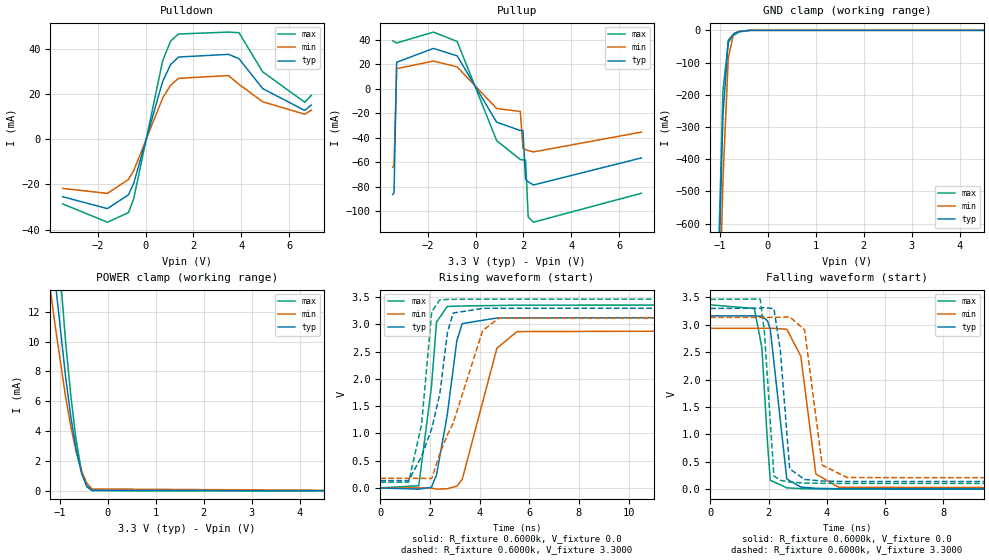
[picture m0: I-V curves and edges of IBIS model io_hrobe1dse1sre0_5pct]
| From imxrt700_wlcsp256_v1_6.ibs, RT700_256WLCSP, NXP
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[Model] io_hrobe1dse1sre0_5pct
|   Model io_hrobe1dse1sre0_5pct
| This model was characterised for following simulation conditions:
| External (pad) voltage:
|   - Typ: 3.3V,   - Min: 3.135V,   - Max: 3.465V
| Library cells for typ/min/max conditions are connected as defined below:
|  PAD_IO - External Pad
|  ipp_do - Core Input
|  ipp_obe - Output Buffer Enable
|  ASRCN3V3[3] - NC
|  ASRCN3V3[4] - NC
|  ASRCP3V3[4] - NC
|  REFAPBIAS3V3 - gnde
|  REFBAMPL3V3 - vdd1v8
|  REFCAMPH3V3 - vdd1v8
|  REFDNBIAS3V3 - vdd1v8
|  REFH3V3 - REFH3V3
|  REFL3V3 - REFL3V3
|  gnde - gnde
|  ipp_dse - vdd
|  ipp_ina235_3v - NC
|  ipp_ina40_3v - NC
|  ipp_ina_mux - NC
|  ipp_ind - NC
|  ipp_ind_1p8v - NC
|  ipp_ind_3v - NC
|  ipp_sre - gnde
|  vdd - vdd
|  vdd1v8 - vdd1v8
|  vdda - vdde3v3
|  vdde3v3 - vdde3v3
| All other pins connected to ground
Model_type I/O
Polarity   Non-Inverting
Enable   Active-High
Vinl =   0.9900V
Vinh =   2.3100V
Vmeas =  1.6500V
Cref =   15.0000pF
Rref =   0.6000k
Vref =   0.0V
C_comp   4.0008pF   3.8187pF   4.1208pF
|C_comp_pullup   0.5645pF   0.7326pF   0.4702pF
|C_comp_pulldown   2.1154pF   2.2153pF   1.8986pF
[Model Spec]
| variable   typ   min   max
Vinh   2.3100V   NA   NA
Vinl   0.9900V   NA   NA
Vref   0.0V   0.0V   0.0V
Cref   15.0000pF   15.0000pF   15.0000pF
Rref   0.6000k   0.6000k   0.6000k
[Receiver Thresholds]
Vcross_high  =   0.0V
Vcross_low  =   0.0V
Vdiff_ac  =   0.0V
Vdiff_dc  =   0.0V
Tdiffslew_ac  =   0.0S
[Temperature Range]   25.0000   0.1250k   -40.0000
[Voltage Range]   3.3000V   3.1350V   3.4650V
[Pullup Reference]   3.3000V   3.1350V   3.4650V
[Pulldown Reference]   0.0V   0.0V   0.0V
[POWER Clamp Reference]   3.3000V   3.1350V   3.4650V
[GND Clamp Reference]   0.0V   0.0V   0.0V
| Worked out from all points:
|   slope of the pulldown table from 0 to 0.495 V, typ, clamps not added: 26.4 ohm
|   slope of the pullup table from 0 to 0.495 V, typ, clamps not added: 28.4 ohm
|   GND clamp passes 1 mA (typ) near -0.50 V on its own axis
|   POWER clamp passes 1 mA (typ) near -0.52 V on its own axis
|   rising waveform, R_fixture 0.6000k, V_fixture 0.0: 20-80 % time 584ps typ, 889ps min, 429ps max; typ from 0 V to 3.16 V
|   rising waveform, R_fixture 0.6000k, V_fixture 3.3000: 20-80 % time 848ps typ, 1.35ns min, 497ps max; typ from 0.133 V to 3.3 V
|   falling waveform, R_fixture 0.6000k, V_fixture 0.0: 20-80 % time 295ps typ, 388ps min, 229ps max; typ from 3.16 V to 0 V
|   falling waveform, R_fixture 0.6000k, V_fixture 3.3000: 20-80 % time 266ps typ, 370ps min, 204ps max; typ from 3.3 V to 0.133 V
[Pulldown]
|Voltage   I(typ)   I(min)   I(max)
-3.465V   -25.43mA   -21.75mA   -28.62mA
-1.595V   -30.68mA   -23.94mA   -36.7mA
-715mV    -24.55mA   -17.79mA   -32.46mA
-495mV    -19.43mA   -13.83mA   -26.26mA
715mV     25.71mA    18.31mA    34.82mA
1.045V    33.07mA    23.94mA    43.49mA
1.375V    36.45mA    27mA       46.65mA
3.465V    37.64mA    28.25mA    47.5mA
3.905V    35.75mA    24.38mA    47.23mA
4.895V    22.48mA    16.65mA    29.91mA
6.655V    12.8mA     11.11mA    16.42mA
6.93V     15.18mA    12.92mA    19.48mA
[Pullup]
|Voltage   I(typ)   I(min)   I(max)
-3.465V   -86.4mA    -64.18mA   39.19mA
-3.41V    -84.92mA   -62.83mA   38.54mA
-3.3V     21.6mA     16.32mA    37.36mA
-1.76V    32.92mA    22.62mA    46.24mA
-770mV    26.81mA    17.8mA     38.61mA
880mV     -27.3mA    -16.17mA   -42.37mA
1.87V     -34.13mA   -18.57mA   -57.85mA
1.98V     -34.24mA   -48.76mA   -58.1mA
2.09V     -74.17mA   -49.75mA   -58.3mA
2.2V      -75.93mA   -50.54mA   -104.8mA
2.42V     -78.62mA   -51.61mA   -109mA
6.93V     -56.52mA   -35.45mA   -85.38mA
[GND_clamp]
|Voltage   I(typ)   I(min)   I(max)
-3.465V   -18.65A    -18.54A    -19.59A
-1.045V   -856.3mA   -1.07A     -789.2mA
-935mV    -262.9mA   -462.2mA   -186.4mA
-825mV    -31.14mA   -87.01mA   -37.16mA
-715mV    -11.21mA   -10.51mA   -15.88mA
-605mV    -3.859mA   -3.519mA   -5.394mA
-385mV    -79.74uA   -219.6uA   -43.96uA
6.93V     0A         0A         0A
[POWER_clamp]
|Voltage   I(typ)   I(min)   I(max)
-3.465V   98.76mA    78.08mA    125.9mA
-1.43V    25.63mA    19.65mA    34.12mA
-1.32V    21.65mA    16.67mA    28.86mA
-1.21V    17.8mA     13.81mA    23.74mA
-1.1V     14.15mA    11.1mA     18.82mA
-880mV    7.624mA    6.286mA    9.977mA
-770mV    4.936mA    4.278mA    6.317mA
-660mV    2.762mA    2.615mA    3.373mA
-550mV    1.207mA    1.351mA    1.33mA
-440mV    332.8uA    528.9uA    282.4uA
-330mV    37.59uA    131uA      15.04uA
6.93V     0A         0A         0A
[Ramp]
| variable   typ   min   max
dV/dt_r  1.8972/0.5839n   1.7621/0.8891n   2.0192/0.4291n
dV/dt_f  1.9001/0.2655n   1.7755/0.3702n   2.0172/0.2036n
R_load = 0.6000k
[Rising Waveform]
R_fixture= 0.6000k
V_fixture= 0.0
V_fixture_min= 0.0
V_fixture_max= 0.0
|time   V(typ)   V(min)   V(max)
0s        75.99nV    1.239uV    52.33nV
1.551ns   -22.58mV   -290.2uV   40.84mV
2.061ns   13.37mV    -3.702mV   1.856V
2.267ns   242.9mV    -21.67mV   3.043V
2.696ns   1.333V     -14.5mV    3.329V
3.085ns   2.704V     32.34mV    3.336V
3.301ns   3.015V     156.9mV    3.338V
4.698ns   3.118V     2.564V     3.347V
5.508ns   3.119V     2.868V     3.353V
60ns      3.162V     2.937V     3.365V
[Rising Waveform]
R_fixture= 0.6000k
V_fixture= 3.3000
V_fixture_min= 3.1350
V_fixture_max= 3.4650
|time   V(typ)   V(min)   V(max)
0s        133.2mV    175.8mV    103mV
1.142ns   132.6mV    175.8mV    106.7mV
1.661ns   578.6mV    175.7mV    1.156V
2.073ns   1.086V     172.2mV    3.234V
2.4ns     1.729V     632.4mV    3.452V
2.705ns   2.853V     973.9mV    3.458V
2.934ns   3.208V     1.185V     3.46V
4.124ns   3.294V     2.887V     3.462V
4.78ns    3.296V     3.116V     3.463V
60ns      3.3V       3.135V     3.465V
[Falling Waveform]
R_fixture= 0.6000k
V_fixture= 0.0
V_fixture_min= 0.0
V_fixture_max= 0.0
|time   V(typ)   V(min)   V(max)
0s        3.162V     2.937V     3.365V
1.513ns   3.163V     2.937V     3.297V
1.771ns   3.157V     2.936V     2.582V
1.961ns   3.076V     2.938V     865.5mV
2.06ns    2.916V     2.938V     162.7mV
2.627ns   185.6mV    2.919V     24.42mV
3.108ns   38.12mV    2.425V     9.959mV
3.622ns   16.21mV    279.1mV    4.572mV
4.409ns   7.077mV    33.36mV    1.775mV
60ns      363.4nV    1.164uV    231.5nV
[Falling Waveform]
R_fixture= 0.6000k
V_fixture= 3.3000
V_fixture_min= 3.1350
V_fixture_max= 3.4650
|time   V(typ)   V(min)   V(max)
0s        3.3V       3.135V     3.465V
1.714ns   3.303V     3.135V     3.47V
1.857ns   3.315V     3.134V     2.872V
2.184ns   3.295V     3.136V     241.2mV
2.403ns   2.54V      3.137V     162.2mV
2.725ns   371.7mV    3.146V     128.6mV
3.238ns   176.7mV    2.907V     112.7mV
3.841ns   148.9mV    440mV      106.9mV
4.693ns   139.6mV    212.2mV    104.4mV
60ns      133.2mV    175.8mV    103mV
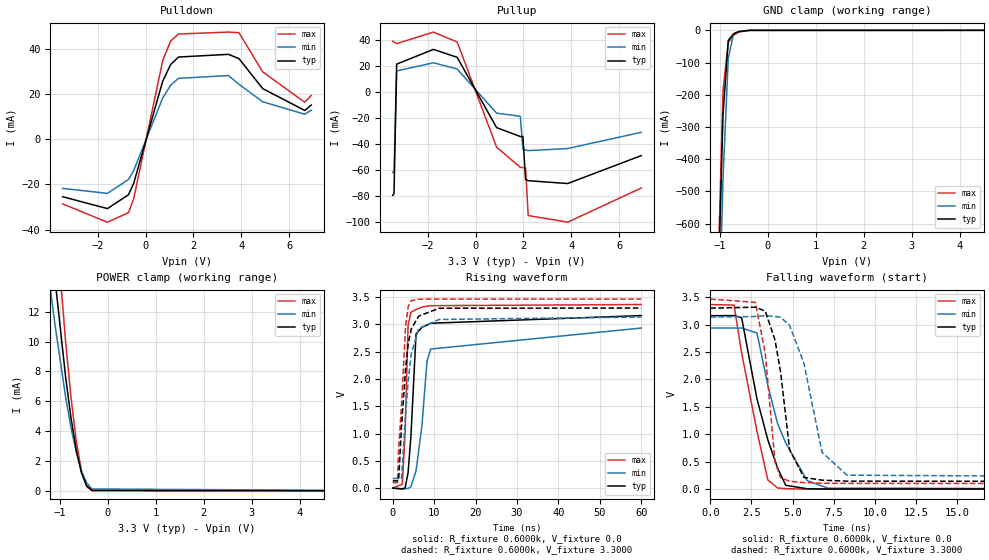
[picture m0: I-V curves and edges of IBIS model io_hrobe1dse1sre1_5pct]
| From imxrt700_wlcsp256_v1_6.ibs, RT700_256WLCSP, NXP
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[Model] io_hrobe1dse1sre1_5pct
|   Model io_hrobe1dse1sre1_5pct
| This model was characterised for following simulation conditions:
| External (pad) voltage:
|   - Typ: 3.3V,   - Min: 3.135V,   - Max: 3.465V
| Library cells for typ/min/max conditions are connected as defined below:
|  PAD_IO - External Pad
|  ipp_do - Core Input
|  ipp_obe - Output Buffer Enable
|  ASRCN3V3[3] - NC
|  ASRCN3V3[4] - NC
|  ASRCP3V3[4] - NC
|  REFAPBIAS3V3 - gnde
|  REFBAMPL3V3 - vdd1v8
|  REFCAMPH3V3 - vdd1v8
|  REFDNBIAS3V3 - vdd1v8
|  REFH3V3 - REFH3V3
|  REFL3V3 - REFL3V3
|  gnde - gnde
|  ipp_dse - vdd
|  ipp_ina235_3v - NC
|  ipp_ina40_3v - NC
|  ipp_ina_mux - NC
|  ipp_ind - NC
|  ipp_ind_1p8v - NC
|  ipp_ind_3v - NC
|  ipp_sre - vdd
|  vdd - vdd
|  vdd1v8 - vdd1v8
|  vdda - vdde3v3
|  vdde3v3 - vdde3v3
| All other pins connected to ground
Model_type I/O
Polarity   Non-Inverting
Enable   Active-High
Vinl =   0.9900V
Vinh =   2.3100V
Vmeas =  1.6500V
Cref =   15.0000pF
Rref =   0.6000k
Vref =   0.0V
C_comp   4.0008pF   3.8187pF   4.1208pF
|C_comp_pullup   0.5642pF   0.7323pF   0.4699pF
|C_comp_pulldown   2.1153pF   2.2151pF   1.8985pF
[Model Spec]
| variable   typ   min   max
Vinh   2.3100V   NA   NA
Vinl   0.9900V   NA   NA
Vref   0.0V   0.0V   0.0V
Cref   15.0000pF   15.0000pF   15.0000pF
Rref   0.6000k   0.6000k   0.6000k
[Receiver Thresholds]
Vcross_high  =   0.0V
Vcross_low  =   0.0V
Vdiff_ac  =   0.0V
Vdiff_dc  =   0.0V
Tdiffslew_ac  =   0.0S
[Temperature Range]   25.0000   0.1250k   -40.0000
[Voltage Range]   3.3000V   3.1350V   3.4650V
[Pullup Reference]   3.3000V   3.1350V   3.4650V
[Pulldown Reference]   0.0V   0.0V   0.0V
[POWER Clamp Reference]   3.3000V   3.1350V   3.4650V
[GND Clamp Reference]   0.0V   0.0V   0.0V
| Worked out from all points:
|   slope of the pulldown table from 0 to 0.495 V, typ, clamps not added: 26.4 ohm
|   slope of the pullup table from 0 to 0.495 V, typ, clamps not added: 28.4 ohm
|   GND clamp passes 1 mA (typ) near -0.50 V on its own axis
|   POWER clamp passes 1 mA (typ) near -0.52 V on its own axis
|   rising waveform, R_fixture 0.6000k, V_fixture 0.0: 20-80 % time 1.18ns typ, 2.11ns min, 743ps max; typ from 0 V to 3.16 V
|   rising waveform, R_fixture 0.6000k, V_fixture 3.3000: 20-80 % time 1.98ns typ, 2.15ns min, 1.44ns max; typ from 0.133 V to 3.3 V
|   falling waveform, R_fixture 0.6000k, V_fixture 0.0: 20-80 % time 1.59ns typ, 1.97ns min, 1.32ns max; typ from 3.16 V to 0 V
|   falling waveform, R_fixture 0.6000k, V_fixture 3.3000: 20-80 % time 830ps typ, 1.24ns min, 622ps max; typ from 3.3 V to 0.133 V
[Pulldown]
|Voltage   I(typ)   I(min)   I(max)
-3.465V   -25.43mA   -21.75mA   -28.62mA
-1.595V   -30.68mA   -23.94mA   -36.7mA
-715mV    -24.55mA   -17.79mA   -32.46mA
-495mV    -19.43mA   -13.83mA   -26.26mA
715mV     25.71mA    18.31mA    34.82mA
1.045V    33.07mA    23.94mA    43.49mA
1.375V    36.45mA    27mA       46.65mA
3.465V    37.64mA    28.25mA    47.5mA
3.905V    35.75mA    24.38mA    47.23mA
4.895V    22.48mA    16.65mA    29.91mA
6.655V    12.8mA     11.11mA    16.42mA
6.93V     15.18mA    12.92mA    19.48mA
[Pullup]
|Voltage   I(typ)   I(min)   I(max)
-3.465V   -79.46mA   -61.86mA   39.19mA
-3.41V    -77.95mA   -60.5mA    38.54mA
-3.3V     21.58mA    16.32mA    37.36mA
-1.76V    32.92mA    22.62mA    46.24mA
-770mV    26.81mA    17.8mA     38.61mA
880mV     -27.3mA    -16.17mA   -42.37mA
1.87V     -34.13mA   -18.57mA   -57.85mA
1.98V     -34.24mA   -43.97mA   -58.1mA
2.09V     -67.14mA   -44.56mA   -58.3mA
2.2V      -68.15mA   -45mA      -94.98mA
3.85V     -70.34mA   -43.4mA    -100.1mA
6.93V     -48.83mA   -30.89mA   -73.76mA
[GND_clamp]
|Voltage   I(typ)   I(min)   I(max)
-3.465V   -18.65A    -18.54A    -19.59A
-1.045V   -856.3mA   -1.07A     -789.2mA
-935mV    -262.9mA   -462.2mA   -186.4mA
-825mV    -31.14mA   -87.01mA   -37.16mA
-715mV    -11.21mA   -10.51mA   -15.88mA
-605mV    -3.859mA   -3.519mA   -5.394mA
-385mV    -79.74uA   -219.6uA   -43.96uA
6.93V     0A         0A         0A
[POWER_clamp]
|Voltage   I(typ)   I(min)   I(max)
-3.465V   98.76mA    78.08mA    125.9mA
-1.43V    25.63mA    19.65mA    34.12mA
-1.32V    21.65mA    16.67mA    28.86mA
-1.21V    17.8mA     13.81mA    23.74mA
-1.1V     14.15mA    11.1mA     18.82mA
-880mV    7.624mA    6.286mA    9.977mA
-770mV    4.936mA    4.278mA    6.317mA
-660mV    2.762mA    2.615mA    3.373mA
-550mV    1.207mA    1.351mA    1.33mA
-440mV    332.8uA    528.9uA    282.4uA
-330mV    37.59uA    131uA      15.04uA
6.93V     0A         0A         0A
[Ramp]
| variable   typ   min   max
dV/dt_r  1.8971/1.1809n   1.7604/2.1112n   2.0192/0.7432n
dV/dt_f  1.9001/0.8297n   1.7755/1.2414n   2.0172/0.6224n
R_load = 0.6000k
[Rising Waveform]
R_fixture= 0.6000k
V_fixture= 0.0
V_fixture_min= 0.0
V_fixture_max= 0.0
|time   V(typ)   V(min)   V(max)
0s        75.99nV    1.239uV    52.33nV
2.317ns   -13.2mV    -19.37mV   71.21mV
2.999ns   2.63mV     -11.29mV   1.012V
3.704ns   280.3mV    -5.481mV   2.973V
4.381ns   928.6mV    22.56mV    3.221V
5.63ns    2.826V     316.7mV    3.274V
7.04ns    2.946V     1.136V     3.317V
8.289ns   2.988V     2.334V     3.336V
9.176ns   3.022V     2.549V     3.344V
60ns      3.162V     2.934V     3.365V
[Rising Waveform]
R_fixture= 0.6000k
V_fixture= 3.3000
V_fixture_min= 3.1350
V_fixture_max= 3.4650
|time   V(typ)   V(min)   V(max)
0s        133.2mV    175.8mV    103mV
1.133ns   132.7mV    175.8mV    100.2mV
1.43ns    137.9mV    175.5mV    700.3mV
2.111ns   1.115V     178.2mV    1.504V
3.119ns   2.197V     1.36V      2.982V
3.752ns   2.654V     1.984V     3.329V
4.48ns    2.917V     2.457V     3.435V
6.256ns   3.151V     2.924V     3.462V
11.18ns   3.297V     3.091V     3.465V
60ns      3.3V       3.135V     3.465V
[Falling Waveform]
R_fixture= 0.6000k
V_fixture= 0.0
V_fixture_min= 0.0
V_fixture_max= 0.0
|time   V(typ)   V(min)   V(max)
0s        3.162V     2.937V     3.365V
1.442ns   3.163V     2.937V     3.355V
1.905ns   3.126V     2.937V     2.488V
2.841ns   1.644V     2.847V     1.05V
3.502ns   896.3mV    1.889V     166.2mV
4.096ns   382.3mV    1.194V     22.18mV
4.585ns   71.28mV    844.2mV    8.003mV
5.885ns   7.845mV    157.8mV    1.347mV
7.155ns   2.857mV    17.25mV    365.8uV
60ns      361.7nV    1.132uV    213.1nV
[Falling Waveform]
R_fixture= 0.6000k
V_fixture= 3.3000
V_fixture_min= 3.1350
V_fixture_max= 3.4650
|time   V(typ)   V(min)   V(max)
0s        3.3V       3.135V     3.465V
2.743ns   3.317V     3.147V     3.405V
3.345ns   3.245V     3.162V     2.469V
3.934ns   2.722V     3.148V     494.9mV
4.277ns   2.133V     3.133V     208.6mV
4.825ns   717.3mV    2.985V     143.9mV
5.697ns   214.1mV    2.292V     118.8mV
6.796ns   164.1mV    671.6mV    109.6mV
8.314ns   145.9mV    254.6mV    105.3mV
60ns      133.2mV    175.8mV    103mV
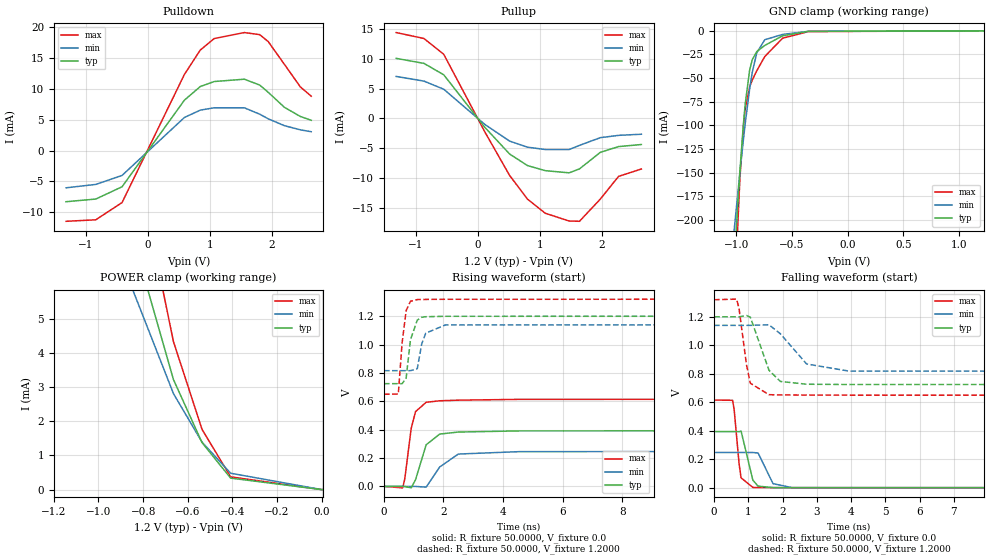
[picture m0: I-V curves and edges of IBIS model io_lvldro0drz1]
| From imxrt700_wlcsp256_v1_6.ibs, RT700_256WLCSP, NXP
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[Model] io_lvldro0drz1
|   Model io_lvldro0drz1
| This model was characterised for following simulation conditions:
| External (pad) voltage:
|   - Typ: 1.2V,   - Min: 1.14V,   - Max: 1.32V
| Library cells for typ/min/max conditions are connected as defined below:
|  ipp_io - External Pad
|  ipp_do - Core Input
|  ipp_obe - Output Buffer Enable
|  config1v21v8 - vdd
|  drive0 - vdd
|  drive1 - gnde
|  gnd - gnd
|  gnde - gnde
|  ncgather - NC
|  vdd - vdd
|  vdde1v8 - vdde1v8
| All other pins connected to ground
Model_type I/O
Polarity   Non-Inverting
Enable   Active-Low
Vinl =   0.3600V
Vinh =   0.8400V
Vmeas =  0.6000V
Cref =   30.0000pF
Rref =   1.0000M
Vref =   1.2000V
C_comp   2.6162pF   2.5656pF   2.7102pF
|C_comp_pullup   1.3386pF   1.3967pF   1.2797pF
|C_comp_pulldown   0.0F   0.0F   0.0F
[Model Spec]
| variable   typ   min   max
Vinh   0.8400V   NA   NA
Vinl   0.3600V   NA   NA
Vref   1.8000V   1.8000V   1.8000V
Cref   30.0000pF   30.0000pF   30.0000pF
Rref   1.0000M   1.0000M   1.0000M
[Temperature Range]   25.0000   0.1250k   -40.0000
[Voltage Range]   1.2000V   1.1400V   1.3200V
[Pullup Reference]   1.2000V   1.1400V   1.3200V
[Pulldown Reference]   0.0V   0.0V   0.0V
[POWER Clamp Reference]   1.2000V   1.1400V   1.3200V
[GND Clamp Reference]   0.0V   0.0V   0.0V
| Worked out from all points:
|   slope of the pulldown table from 0 to 0.18 V, typ, clamps not added: 68.1 ohm
|   slope of the pullup table from 0 to 0.18 V, typ, clamps not added: 77.3 ohm
|   GND clamp passes 1 mA (typ) near -0.39 V on its own axis
|   POWER clamp passes 1 mA (typ) near -0.49 V on its own axis
|   rising waveform, R_fixture 50.0000, V_fixture 0.0: 20-80 % time 385ps typ, 497ps min, 260ps max; typ from 0 V to 0.395 V
|   rising waveform, R_fixture 50.0000, V_fixture 1.2000: 20-80 % time 204ps typ, 224ps min, 168ps max; typ from 0.724 V to 1.2 V
|   falling waveform, R_fixture 50.0000, V_fixture 0.0: 20-80 % time 210ps typ, 279ps min, 142ps max; typ from 0.395 V to 0 V
|   falling waveform, R_fixture 50.0000, V_fixture 1.2000: 20-80 % time 394ps typ, 670ps min, 232ps max; typ from 1.2 V to 0.724 V
[Pulldown]
|Voltage   I(typ)   I(min)   I(max)
-1.32V    -8.289mA   -6.034mA   -11.47mA
-840mV    -7.857mA   -5.481mA   -11.23mA
-416mV    -5.864mA   -4.024mA   -8.427mA
592mV     8.203mA    5.391mA    12.39mA
848mV     10.41mA    6.579mA    16.33mA
1.072V    11.22mA    6.956mA    18.2mA
1.56V     11.6mA     6.952mA    19.17mA
1.808V    10.64mA    5.919mA    18.83mA
1.944V    9.481mA    5.171mA    17.72mA
2.208V    7.023mA    4.049mA    13.99mA
2.464V    5.549mA    3.381mA    10.35mA
2.64V     4.928mA    3.07mA     8.834mA
[Pullup]
|Voltage   I(typ)   I(min)   I(max)
-1.32V    10.04mA    7.02mA     14.35mA
-872mV    9.204mA    6.244mA    13.36mA
-552mV    7.296mA    4.882mA    10.72mA
112mV     -1.487mA   -996.7uA   -2.255mA
512mV     -5.94mA    -3.781mA   -9.523mA
800mV     -7.872mA   -4.795mA   -13.47mA
1.088V    -8.721mA   -5.191mA   -15.84mA
1.472V    -9.083mA   -5.2mA     -17.13mA
1.64V     -8.428mA   -4.5mA     -17.18mA
1.976V    -5.664mA   -3.21mA    -13.48mA
2.272V    -4.697mA   -2.822mA   -9.675mA
2.64V     -4.353mA   -2.634mA   -8.444mA
[GND_clamp]
|Voltage   I(typ)   I(min)   I(max)
-1.32V    -824mA     -526.2mA   -1.227A
-1.032V   -269.6mA   -225.5mA   -323.8mA
-968mV    -148.5mA   -150.4mA   -156.4mA
-936mV    -98.26mA   -114.7mA   -100.6mA
-920mV    -77.35mA   -98.01mA   -82.61mA
-880mV    -41.26mA   -61.23mA   -59.24mA
-856mV    -30.33mA   -43.55mA   -51.86mA
-816mV    -21.94mA   -23.19mA   -42.16mA
-744mV    -15.43mA   -9.413mA   -27.16mA
-584mV    -5.259mA   -3.813mA   -7.801mA
-352mV    -567.9uA   -545.2uA   -812.4uA
1.224V    19.17nA    663.1nA    12.5nA
[POWER_clamp]
|Voltage   I(typ)   I(min)   I(max)
-1.32V    19.88mA    14.94mA    27.37mA
-1.048V   11.99mA    9.201mA    16.54mA
-664mV    3.218mA    2.807mA    4.327mA
-536mV    1.374mA    1.388mA    1.761mA
-408mV    336uA      479.3uA    373.8uA
0V        17.28nA    129.7nA    13.53nA
8mV       16.9nA     117.4nA    13.43nA
[Ramp]
| variable   typ   min   max
dV/dt_r  0.2369/0.3848n   0.1490/0.4965n   0.3696/0.2595n
dV/dt_f  0.2855/0.3945n   0.1945/0.6701n   0.4023/0.2321n
R_load = 50.0000
[Rising Waveform]
R_fixture= 50.0000
V_fixture= 0.0
V_fixture_min= 0.0
V_fixture_max= 0.0
|time   V(typ)   V(min)   V(max)
0s        28.83nV    1.74uV     3.209nV
628.8ps   -22.9uV    651.8nV    -10.27mV
701.2ps   -1.445mV   1.765uV    53.97mV
913.9ps   -9.706mV   2.335uV    407.9mV
1.061ns   47.09mV    -247.3uV   527mV
1.418ns   293.4mV    -5.199mV   592.9mV
1.874ns   369mV      137mV      603.5mV
2.497ns   383.1mV    228mV      607.8mV
4.53ns    391.1mV    244.9mV    613.4mV
60ns      394.8mV    248.3mV    616mV
[Rising Waveform]
R_fixture= 50.0000
V_fixture= 1.2000
V_fixture_min= 1.1400
V_fixture_max= 1.3200
|time   V(typ)   V(min)   V(max)
0s        724.2mV    815.8mV    649.6mV
482.2ps   724.2mV    815.8mV    651.3mV
610.2ps   724.2mV    815.8mV    1.012V
745.6ps   763.3mV    815.8mV    1.239V
891.2ps   1.034V     815.8mV    1.305V
1.12ns    1.172V     829.8mV    1.317V
1.269ns   1.192V     1.004V     1.317V
1.404ns   1.196V     1.08V      1.318V
2.064ns   1.199V     1.138V     1.319V
60ns      1.2V       1.14V      1.32V
[Falling Waveform]
R_fixture= 50.0000
V_fixture= 0.0
V_fixture_min= 0.0
V_fixture_max= 0.0
|time   V(typ)   V(min)   V(max)
0s        394.8mV    248.3mV    616mV
539.7ps   394.8mV    248.3mV    614.3mV
586.7ps   394.8mV    248.3mV    549.1mV
731.4ps   394.4mV    248.3mV    167mV
788.1ps   398.8mV    248.3mV    70.4mV
1.132ns   53.92mV    248mV      3.068mV
1.285ns   12.08mV    244.7mV    2.27mV
1.721ns   1.711mV    29.52mV    1.683mV
2.269ns   1.069mV    1.909mV    1.294mV
60ns      267.6nV    3.849uV    21.83nV
[Falling Waveform]
R_fixture= 50.0000
V_fixture= 1.2000
V_fixture_min= 1.1400
V_fixture_max= 1.3200
|time   V(typ)   V(min)   V(max)
0s        1.2V       1.14V      1.32V
659.4ps   1.2V       1.14V      1.324V
729.1ps   1.2V       1.14V      1.258V
946.3ps   1.209V     1.14V      863.8mV
1.058ns   1.198V     1.14V      734.3mV
1.603ns   825mV      1.144V     653.7mV
1.935ns   746.6mV    1.081V     651.9mV
2.701ns   727mV      869.1mV    651mV
3.937ns   725.1mV    819.1mV    650.3mV
60ns      724.2mV    815.8mV    649.6mV
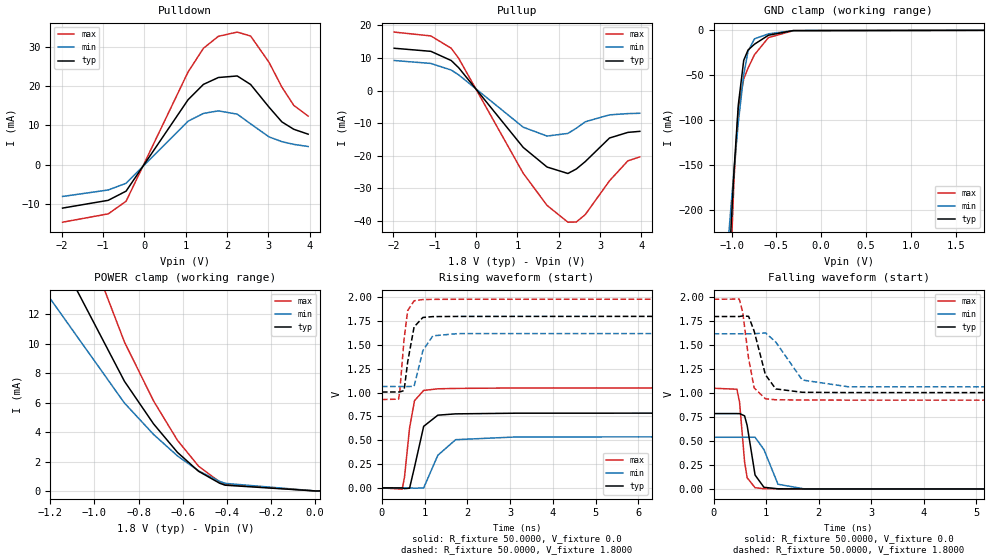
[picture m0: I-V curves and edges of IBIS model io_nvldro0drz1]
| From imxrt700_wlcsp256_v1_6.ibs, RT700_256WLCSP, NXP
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[Model] io_nvldro0drz1
|   Model io_nvldro0drz1
| This model was characterised for following simulation conditions:
| External (pad) voltage:
|   - Typ: 1.8V,   - Min: 1.62V,   - Max: 1.98V
| Library cells for typ/min/max conditions are connected as defined below:
|  ipp_io - External Pad
|  ipp_do - Core Input
|  ipp_obe - Output Buffer Enable
|  config1v21v8 - gnde
|  drive0 - vdd
|  drive1 - gnd
|  gnd - gnd
|  gnde - gnde
|  ncgather - NC
|  vdd - vdd
|  vdde1v8 - vdde1v8
| All other pins connected to ground
Model_type I/O
Polarity   Non-Inverting
Enable   Active-Low
Vinl =   0.5400V
Vinh =   1.2600V
Vmeas =  0.9000V
Cref =   30.0000pF
Rref =   1.0000M
Vref =   1.8000V
C_comp   2.6145pF   2.5654pF   2.7098pF
|C_comp_pullup   1.3315pF   1.3901pF   1.2757pF
|C_comp_pulldown   0.0F   0.0F   0.0F
[Model Spec]
| variable   typ   min   max
Vinh   1.2600V   NA   NA
Vinl   0.5400V   NA   NA
Vref   1.8000V   1.8000V   1.8000V
Cref   30.0000pF   30.0000pF   30.0000pF
Rref   1.0000M   1.0000M   1.0000M
[Temperature Range]   25.0000   0.1250k   -40.0000
[Voltage Range]   1.8000V   1.6200V   1.9800V
[Pullup Reference]   1.8000V   1.6200V   1.9800V
[Pulldown Reference]   0.0V   0.0V   0.0V
[POWER Clamp Reference]   1.8000V   1.6200V   1.9800V
[GND Clamp Reference]   0.0V   0.0V   0.0V
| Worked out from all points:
|   slope of the pulldown table from 0 to 0.27 V, typ, clamps not added: 60.2 ohm
|   slope of the pullup table from 0 to 0.27 V, typ, clamps not added: 60.4 ohm
|   GND clamp passes 1 mA (typ) near -0.39 V on its own axis
|   POWER clamp passes 1 mA (typ) near -0.49 V on its own axis
|   rising waveform, R_fixture 50.0000, V_fixture 0.0: 20-80 % time 224ps typ, 335ps min, 166ps max; typ from 0 V to 0.788 V
|   rising waveform, R_fixture 50.0000, V_fixture 1.8000: 20-80 % time 162ps typ, 203ps min, 127ps max; typ from 1 V to 1.8 V
|   falling waveform, R_fixture 50.0000, V_fixture 0.0: 20-80 % time 135ps typ, 204ps min, 99.2ps max; typ from 0.788 V to 0 V
|   falling waveform, R_fixture 50.0000, V_fixture 1.8000: 20-80 % time 232ps typ, 394ps min, 158ps max; typ from 1.8 V to 1 V
[Pulldown]
|Voltage   I(typ)   I(min)   I(max)
-1.98V    -11.04mA   -8.08mA    -14.63mA
-876mV    -9.061mA   -6.427mA   -12.51mA
-444mV    -6.726mA   -4.719mA   -9.308mA
1.056V    16.56mA    11.09mA    23.63mA
1.428V    20.47mA    13.07mA    29.67mA
1.788V    22.21mA    13.72mA    32.7mA
2.244V    22.61mA    12.88mA    33.78mA
2.568V    20.44mA    10.42mA    32.78mA
3.012V    14.68mA    7.098mA    26.1mA
3.324V    10.91mA    5.875mA    19.78mA
3.612V    9.029mA    5.186mA    15.11mA
3.96V     7.783mA    4.642mA    12.39mA
[Pullup]
|Voltage   I(typ)   I(min)   I(max)
-1.98V    12.98mA    9.216mA    17.94mA
-1.092V   12.03mA    8.315mA    16.76mA
-600mV    9.201mA    6.277mA    12.96mA
-420mV    6.988mA    4.802mA    9.866mA
1.14V     -17.46mA   -11.26mA   -25.4mA
1.716V    -23.48mA   -13.98mA   -35.26mA
2.22V     -25.47mA   -13.17mA   -40.42mA
2.424V    -24.09mA   -11.57mA   -40.37mA
2.64V     -21.82mA   -9.595mA   -38.1mA
3.228V    -14.57mA   -7.467mA   -27.69mA
3.672V    -12.85mA   -7.086mA   -21.58mA
3.96V     -12.53mA   -6.981mA   -20.38mA
[GND_clamp]
|Voltage   I(typ)   I(min)   I(max)
-1.98V    -2.304A    -1.314A    -3.648A
-1.188V   -579.3mA   -402.9mA   -809.8mA
-1.068V   -345.9mA   -273.9mA   -436.6mA
-1.02V    -246.9mA   -214.1mA   -290.1mA
-972mV    -156.3mA   -155.7mA   -166mA
-924mV    -82.86mA   -102.6mA   -86.85mA
-864mV    -33.43mA   -49.36mA   -54.12mA
-816mV    -21.98mA   -23.37mA   -42.16mA
-744mV    -15.43mA   -9.445mA   -27.16mA
-588mV    -5.426mA   -3.899mA   -8.058mA
-312mV    -266.2uA   -304.2uA   -358.5uA
1.812V    32.97nA    19.93uA    18.44nA
[POWER_clamp]
|Voltage   I(typ)   I(min)   I(max)
-1.98V    42.39mA    31.81mA    57.35mA
-1.428V   23.67mA    17.88mA    32.24mA
-864mV    7.459mA    5.979mA    10.13mA
-732mV    4.558mA    3.841mA    6.117mA
-624mV    2.625mA    2.385mA    3.446mA
-528mV    1.334mA    1.364mA    1.682mA
-432mV    519.4uA    646.1uA    606.8uA
-408mV    390uA      515.7uA    447uA
0V        28.12nA    179.8nA    22.83nA
24mV      22.85nA    114.3nA    21.08nA
[Ramp]
| variable   typ   min   max
dV/dt_r  0.4728/0.2237n   0.3246/0.3349n   0.6315/0.1663n
dV/dt_f  0.4767/0.2323n   0.3343/0.3938n   0.6320/0.1584n
R_load = 50.0000
[Rising Waveform]
R_fixture= 50.0000
V_fixture= 0.0
V_fixture_min= 0.0
V_fixture_max= 0.0
|time   V(typ)   V(min)   V(max)
0s        306.6nV    3.163uV    635.4nV
473.6ps   -91.61uV   2.901uV    -13.3mV
528.5ps   -7.506mV   3.979uV    113.6mV
646.4ps   -3.534mV   -9.451uV   627.1mV
762.9ps   218.8mV    -3.602mV   915.1mV
976.9ps   645.6mV    234.4uV    1.022V
1.308ns   762.6mV    342mV      1.039V
1.725ns   776.3mV    505.6mV    1.043V
3.161ns   783.4mV    534.6mV    1.048V
60ns      788.1mV    541mV      1.052V
[Rising Waveform]
R_fixture= 50.0000
V_fixture= 1.8000
V_fixture_min= 1.6200
V_fixture_max= 1.9800
|time   V(typ)   V(min)   V(max)
0s        1.005V     1.063V     926.6mV
389.6ps   1.006V     1.063V     930.6mV
418.6ps   1.006V     1.063V     1.017V
518.4ps   1.021V     1.063V     1.56V
602.2ps   1.32V      1.063V     1.858V
752.7ps   1.688V     1.065V     1.962V
957.7ps   1.787V     1.439V     1.975V
1.191ns   1.796V     1.594V     1.977V
1.777ns   1.798V     1.618V     1.978V
60ns      1.8V       1.62V      1.98V
[Falling Waveform]
R_fixture= 50.0000
V_fixture= 0.0
V_fixture_min= 0.0
V_fixture_max= 0.0
|time   V(typ)   V(min)   V(max)
0s        788.1mV    541mV      1.052V
444.3ps   788mV      541mV      1.042V
494.8ps   787.8mV    541mV      907.2mV
590.2ps   764.6mV    541mV      285.7mV
639.2ps   664.2mV    541mV      119mV
790ps     147.1mV    541.1mV    15.22mV
959.3ps   19.54mV    412.4mV    4.977mV
1.226ns   3.89mV     51.34mV    3.323mV
1.729ns   2.284mV    2.864mV    2.566mV
60ns      645.4nV    6.894uV    664.3nV
[Falling Waveform]
R_fixture= 50.0000
V_fixture= 1.8000
V_fixture_min= 1.6200
V_fixture_max= 1.9800
|time   V(typ)   V(min)   V(max)
0s        1.8V       1.62V      1.98V
488.7ps   1.8V       1.62V      1.982V
555.1ps   1.806V     1.62V      1.843V
666.7ps   1.802V     1.62V      1.364V
772.4ps   1.648V     1.62V      1.056V
987.2ps   1.193V     1.63V      941.8mV
1.184ns   1.045V     1.534V     932.1mV
1.689ns   1.01V      1.138V     929.4mV
2.572ns   1.007V     1.067V     928.3mV
60ns      1.005V     1.063V     926.6mV
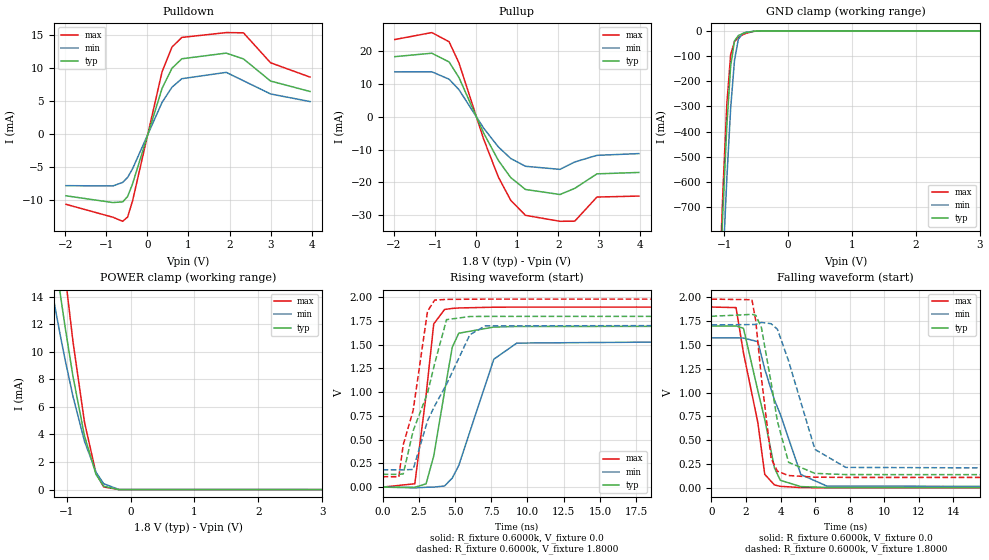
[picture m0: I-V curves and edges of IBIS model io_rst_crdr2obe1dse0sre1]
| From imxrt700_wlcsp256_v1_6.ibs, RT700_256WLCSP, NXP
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[Model] io_rst_crdr2obe1dse0sre1
|   Model io_rst_crdr2obe1dse0sre1
| This model was characterised for following simulation conditions:
| External (pad) voltage:
|   - Typ: 1.8V,   - Min: 1.71V,   - Max: 1.98V
| Library cells for typ/min/max conditions are connected as defined below:
|  PAD_RST - External Pad
|  ipp_do - Core Input
|  ipp_obe - Output Buffer Enable
|  ASRCN3V3[3] - NC
|  ASRCN3V3[4] - NC
|  ASRCP3V3[4] - NC
|  REFAPBIAS3V3 - gnde
|  REFBAMPL3V3 - vdd1v8
|  REFCAMPH3V3 - vdd1v8
|  REFDNBIAS3V3 - vdd1v8
|  REFH3V3 - REFH3V3
|  REFL3V3 - REFL3V3
|  gnde - gnde
|  ipp_dse - gnde
|  ipp_ina235_3v - NC
|  ipp_ina40_3v - NC
|  ipp_ina_mux - NC
|  ipp_ind - NC
|  ipp_ind_1p8v - NC
|  ipp_ind_3v - NC
|  ipp_sre - vdd
|  vdd - vdd
|  vdd1v8 - vdd1v8
|  vdda - vdde3v3
|  vdde3v3 - vdde3v3
| All other pins connected to ground
Model_type I/O
Polarity   Non-Inverting
Enable   Active-High
Vinl =   0.5400V
Vinh =   1.2600V
Vmeas =  0.9000V
Cref =   15.0000pF
Rref =   0.6000k
Vref =   0.0V
C_comp   3.9797pF   3.7947pF   4.1049pF
|C_comp_pullup   0.4868pF   0.5823pF   0.4755pF
|C_comp_pulldown   2.0822pF   2.1674pF   1.8518pF
[Model Spec]
| variable   typ   min   max
Vinh   1.2600V   NA   NA
Vinl   0.5400V   NA   NA
Vref   0.0V   0.0V   0.0V
Cref   15.0000pF   15.0000pF   15.0000pF
Rref   0.6000k   0.6000k   0.6000k
[Receiver Thresholds]
Vcross_high  =   0.0V
Vcross_low  =   0.0V
Vdiff_ac  =   0.0V
Vdiff_dc  =   0.0V
Tdiffslew_ac  =   0.0S
[Temperature Range]   25.0000   0.1250k   -40.0000
[Voltage Range]   1.8000V   1.7100V   1.9800V
[Pullup Reference]   1.8000V   1.7100V   1.9800V
[Pulldown Reference]   0.0V   0.0V   0.0V
[POWER Clamp Reference]   1.8000V   1.7100V   1.9800V
[GND Clamp Reference]   0.0V   0.0V   0.0V
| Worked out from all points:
|   slope of the pulldown table from 0 to 0.27 V, typ, clamps not added: 50.4 ohm
|   slope of the pullup table from 0 to 0.27 V, typ, clamps not added: 37.4 ohm
|   GND clamp passes 1 mA (typ) near -0.50 V on its own axis
|   POWER clamp passes 1 mA (typ) near -0.53 V on its own axis
|   rising waveform, R_fixture 0.6000k, V_fixture 0.0: 20-80 % time 1.11ns typ, 1.96ns min, 753ps max; typ from 0 V to 1.7 V
|   rising waveform, R_fixture 0.6000k, V_fixture 1.8000: 20-80 % time 2ns typ, 2.83ns min, 1.43ns max; typ from 0.135 V to 1.8 V
|   falling waveform, R_fixture 0.6000k, V_fixture 0.0: 20-80 % time 1.3ns typ, 1.7ns min, 1.14ns max; typ from 1.7 V to 0 V
|   falling waveform, R_fixture 0.6000k, V_fixture 1.8000: 20-80 % time 965ps typ, 1.43ns min, 656ps max; typ from 1.8 V to 0.135 V
[Pulldown]
|Voltage   I(typ)   I(min)   I(max)
-1.98V    -9.436mA   -7.894mA   -10.73mA
-840mV    -10.46mA   -7.944mA   -12.69mA
-600mV    -10.36mA   -7.4mA     -13.31mA
-480mV    -9.54mA    -6.639mA   -12.65mA
-360mV    -7.618mA   -5.325mA   -10.21mA
360mV     6.913mA    4.777mA    9.448mA
600mV     9.943mA    7.063mA    13.16mA
840mV     11.38mA    8.355mA    14.62mA
1.92V     12.24mA    9.317mA    15.36mA
2.34V     11.36mA    8.04mA     15.32mA
3V        7.996mA    6.036mA    10.77mA
3.96V     6.411mA    4.879mA    8.598mA
[Pullup]
|Voltage   I(typ)   I(min)   I(max)
-1.98V    18.38mA    13.75mA    23.61mA
-1.08V    19.43mA    13.76mA    25.73mA
-660mV    16.76mA    11.5mA     22.93mA
-420mV    12.02mA    8.321mA    16.48mA
180mV     -4.905mA   -3.419mA   -6.743mA
540mV     -13.3mA    -9.177mA   -18.38mA
840mV     -18.52mA   -12.69mA   -25.44mA
1.2V      -22.16mA   -15.08mA   -30.05mA
2.04V     -23.69mA   -16.02mA   -31.87mA
2.4V      -21.82mA   -13.76mA   -31.82mA
2.94V     -17.39mA   -11.74mA   -24.47mA
3.96V     -16.96mA   -11.21mA   -24.17mA
[GND_clamp]
|Voltage   I(typ)   I(min)   I(max)
-1.98V    -7.543A    -7.6A      -7.897A
-1.08V    -1.077A    -1.286A    -1.025A
-1.02V    -705.3mA   -921.3mA   -628.8mA
-960mV    -377.1mA   -587.4mA   -291.7mA
-900mV    -139.2mA   -307mA     -94.38mA
-840mV    -40.12mA   -117mA     -42.82mA
-780mV    -18.81mA   -33.95mA   -26.13mA
-720mV    -11.86mA   -11.44mA   -16.78mA
-660mV    -7.061mA   -5.737mA   -9.992mA
-540mV    -1.684mA   -1.901mA   -2.15mA
-420mV    -207.1uA   -403.7uA   -160.6uA
3.96V     0A         0A         0A
[POWER_clamp]
|Voltage   I(typ)   I(min)   I(max)
-1.98V    46.79mA    35.94mA    61.38mA
-1.32V    21.77mA    16.85mA    28.91mA
-1.2V     17.57mA    13.71mA    23.33mA
-1.14V    15.55mA    12.2mA     20.62mA
-1.08V    13.59mA    10.75mA    17.99mA
-1.02V    11.7mA     9.353mA    15.46mA
-900mV    8.209mA    6.76mA     10.73mA
-720mV    3.898mA    3.51mA     4.887mA
-540mV    1.103mA    1.267mA    1.195mA
-420mV    244.5uA    429.2uA    190.6uA
-180mV    280.9nA    5.273uA    26.8nA
3.96V     0A         0A         0A
[Ramp]
| variable   typ   min   max
dV/dt_r  1.0186/1.1116n   0.9439/1.9604n   1.1383/0.7527n
dV/dt_f  0.9990/0.9648n   0.9166/1.4306n   1.1224/0.6560n
R_load = 0.6000k
[Rising Waveform]
R_fixture= 0.6000k
V_fixture= 0.0
V_fixture_min= 0.0
V_fixture_max= 0.0
|time   V(typ)   V(min)   V(max)
0s        115.1nV    3.181uV    43.69nV
2.221ns   -2.066mV   -8.009mV   35.17mV
2.996ns   34.49mV    -1.821mV   966.4mV
3.527ns   327.8mV    -289.8uV   1.719V
4.275ns   1.007V     12.01mV    1.871V
4.807ns   1.474V     95.6mV     1.882V
5.255ns   1.621V     228.4mV    1.887V
7.673ns   1.686V     1.347V     1.895V
9.265ns   1.692V     1.517V     1.896V
60ns      1.698V     1.573V     1.897V
[Rising Waveform]
R_fixture= 0.6000k
V_fixture= 1.8000
V_fixture_min= 1.7100
V_fixture_max= 1.9800
|time   V(typ)   V(min)   V(max)
0s        135mV      182.4mV    109.3mV
1.117ns   134.1mV    182.3mV    109mV
1.42ns    138.7mV    181.8mV    446mV
2.104ns   592mV      185.4mV    806.9mV
3.098ns   991.5mV    698.8mV    1.853V
3.593ns   1.302V     856.1mV    1.97V
4.41ns    1.764V     1.083V     1.977V
6.021ns   1.797V     1.605V     1.979V
7.083ns   1.798V     1.698V     1.98V
60ns      1.8V       1.71V      1.98V
[Falling Waveform]
R_fixture= 0.6000k
V_fixture= 0.0
V_fixture_min= 0.0
V_fixture_max= 0.0
|time   V(typ)   V(min)   V(max)
0s        1.698V     1.573V     1.897V
1.42ns    1.699V     1.573V     1.891V
1.851ns   1.674V     1.572V     1.416V
2.684ns   1.018V     1.534V     683.8mV
3.081ns   719.2mV    1.246V     142.1mV
3.64ns    211.4mV    924.5mV    30.97mV
3.983ns   79.42mV    772.1mV    15.99mV
5.17ns    13.14mV    140mV      3.023mV
6.679ns   4.052mV    18.81mV    560.8uV
60ns      7.065uV    14.69uV    3.068uV
[Falling Waveform]
R_fixture= 0.6000k
V_fixture= 1.8000
V_fixture_min= 1.7100
V_fixture_max= 1.9800
|time   V(typ)   V(min)   V(max)
0s        1.8V       1.71V      1.98V
2.341ns   1.82V      1.713V     1.974V
2.562ns   1.81V      1.715V     1.753V
2.886ns   1.683V     1.736V     1.158V
3.454ns   1.102V     1.722V     307.1mV
3.816ns   696.7mV    1.664V     174.3mV
4.46ns    268.1mV    1.332V     129.5mV
5.985ns   152.1mV    403.7mV    112.1mV
7.767ns   139.3mV    214.6mV    109.6mV
60ns      135mV      182.4mV    109.3mV
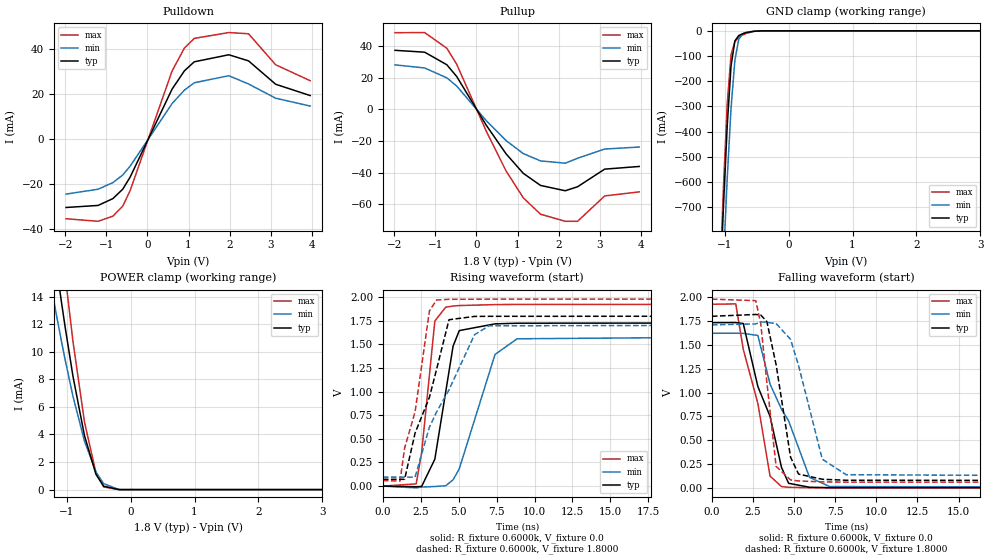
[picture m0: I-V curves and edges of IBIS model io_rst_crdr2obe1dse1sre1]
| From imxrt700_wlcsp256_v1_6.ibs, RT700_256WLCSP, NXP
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[Model] io_rst_crdr2obe1dse1sre1
|   Model io_rst_crdr2obe1dse1sre1
| This model was characterised for following simulation conditions:
| External (pad) voltage:
|   - Typ: 1.8V,   - Min: 1.71V,   - Max: 1.98V
| Library cells for typ/min/max conditions are connected as defined below:
|  PAD_RST - External Pad
|  ipp_do - Core Input
|  ipp_obe - Output Buffer Enable
|  ASRCN3V3[3] - NC
|  ASRCN3V3[4] - NC
|  ASRCP3V3[4] - NC
|  REFAPBIAS3V3 - gnde
|  REFBAMPL3V3 - vdd1v8
|  REFCAMPH3V3 - vdd1v8
|  REFDNBIAS3V3 - vdd1v8
|  REFH3V3 - REFH3V3
|  REFL3V3 - REFL3V3
|  gnde - gnde
|  ipp_dse - vdd
|  ipp_ina235_3v - NC
|  ipp_ina40_3v - NC
|  ipp_ina_mux - NC
|  ipp_ind - NC
|  ipp_ind_1p8v - NC
|  ipp_ind_3v - NC
|  ipp_sre - vdd
|  vdd - vdd
|  vdd1v8 - vdd1v8
|  vdda - vdde3v3
|  vdde3v3 - vdde3v3
| All other pins connected to ground
Model_type I/O
Polarity   Non-Inverting
Enable   Active-High
Vinl =   0.5400V
Vinh =   1.2600V
Vmeas =  0.9000V
Cref =   15.0000pF
Rref =   0.6000k
Vref =   0.0V
C_comp   3.9797pF   3.7947pF   4.1049pF
|C_comp_pullup   0.4869pF   0.5824pF   0.4756pF
|C_comp_pulldown   2.0821pF   2.1672pF   1.8517pF
[Model Spec]
| variable   typ   min   max
Vinh   1.2600V   NA   NA
Vinl   0.5400V   NA   NA
Vref   0.0V   0.0V   0.0V
Cref   15.0000pF   15.0000pF   15.0000pF
Rref   0.6000k   0.6000k   0.6000k
[Receiver Thresholds]
Vcross_high  =   0.0V
Vcross_low  =   0.0V
Vdiff_ac  =   0.0V
Vdiff_dc  =   0.0V
Tdiffslew_ac  =   0.0S
[Temperature Range]   25.0000   0.1250k   -40.0000
[Voltage Range]   1.8000V   1.7100V   1.9800V
[Pullup Reference]   1.8000V   1.7100V   1.9800V
[Pulldown Reference]   0.0V   0.0V   0.0V
[POWER Clamp Reference]   1.8000V   1.7100V   1.9800V
[GND Clamp Reference]   0.0V   0.0V   0.0V
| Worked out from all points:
|   slope of the pulldown table from 0 to 0.27 V, typ, clamps not added: 25.6 ohm
|   slope of the pullup table from 0 to 0.27 V, typ, clamps not added: 23.8 ohm
|   GND clamp passes 1 mA (typ) near -0.50 V on its own axis
|   POWER clamp passes 1 mA (typ) near -0.53 V on its own axis
|   rising waveform, R_fixture 0.6000k, V_fixture 0.0: 20-80 % time 1.02ns typ, 1.78ns min, 691ps max; typ from 0 V to 1.73 V
|   rising waveform, R_fixture 0.6000k, V_fixture 1.8000: 20-80 % time 1.99ns typ, 2.88ns min, 1.39ns max; typ from 0.072 V to 1.8 V
|   falling waveform, R_fixture 0.6000k, V_fixture 0.0: 20-80 % time 1.8ns typ, 2.26ns min, 1.49ns max; typ from 1.73 V to 0 V
|   falling waveform, R_fixture 0.6000k, V_fixture 1.8000: 20-80 % time 938ps typ, 1.38ns min, 686ps max; typ from 1.8 V to 0.072 V
[Pulldown]
|Voltage   I(typ)   I(min)   I(max)
-1.98V    -30.4mA    -24.44mA   -35.4mA
-1.2V     -29.49mA   -22.28mA   -36.54mA
-840mV    -26.45mA   -19.34mA   -34.25mA
-600mV    -22.26mA   -15.94mA   -29.79mA
-420mV    -16.87mA   -12.03mA   -22.87mA
600mV     22.22mA    15.79mA    30.28mA
900mV     30.36mA    21.79mA    40.52mA
1.14V     34.38mA    25.06mA    44.79mA
1.98V     37.51mA    28.2mA     47.38mA
2.46V     34.79mA    24.52mA    46.85mA
3.12V     24.4mA     18.2mA     33.06mA
3.96V     19.37mA    14.7mA     25.97mA
[Pullup]
|Voltage   I(typ)   I(min)   I(max)
-1.98V    37.17mA    27.99mA    48.3mA
-1.26V    36mA       26.04mA    48.37mA
-720mV    28.06mA    19.81mA    38.46mA
-480mV    20.65mA    14.61mA    28.37mA
240mV     -10.13mA   -7.213mA   -13.9mA
720mV     -28.1mA    -19.75mA   -38.89mA
1.14V     -40.44mA   -27.98mA   -55.87mA
1.56V     -48.07mA   -32.59mA   -66.23mA
2.16V     -51.42mA   -34.03mA   -70.68mA
2.46V     -48.9mA    -30.94mA   -70.69mA
3.12V     -37.78mA   -25.09mA   -54.69mA
3.96V     -36.1mA    -23.85mA   -52.12mA
[GND_clamp]
|Voltage   I(typ)   I(min)   I(max)
-1.98V    -7.543A    -7.6A      -7.897A
-1.08V    -1.077A    -1.286A    -1.025A
-1.02V    -705.3mA   -921.3mA   -628.8mA
-960mV    -377.1mA   -587.4mA   -291.7mA
-900mV    -139.2mA   -307mA     -94.38mA
-840mV    -40.12mA   -117mA     -42.82mA
-780mV    -18.81mA   -33.95mA   -26.13mA
-720mV    -11.86mA   -11.44mA   -16.78mA
-660mV    -7.061mA   -5.737mA   -9.992mA
-540mV    -1.684mA   -1.901mA   -2.15mA
-420mV    -207.1uA   -403.7uA   -160.6uA
3.96V     0A         0A         0A
[POWER_clamp]
|Voltage   I(typ)   I(min)   I(max)
-1.98V    46.79mA    35.94mA    61.38mA
-1.32V    21.77mA    16.85mA    28.91mA
-1.2V     17.57mA    13.71mA    23.33mA
-1.14V    15.55mA    12.2mA     20.62mA
-1.08V    13.59mA    10.75mA    17.99mA
-1.02V    11.7mA     9.353mA    15.46mA
-900mV    8.209mA    6.76mA     10.73mA
-720mV    3.898mA    3.51mA     4.887mA
-540mV    1.103mA    1.267mA    1.195mA
-420mV    244.5uA    429.2uA    190.6uA
-180mV    280.9nA    5.273uA    26.8nA
3.96V     0A         0A         0A
[Ramp]
| variable   typ   min   max
dV/dt_r  1.0396/1.0203n   0.9730/1.7848n   1.1554/0.6905n
dV/dt_f  1.0366/0.9381n   0.9689/1.3823n   1.1528/0.6864n
R_load = 0.6000k
[Rising Waveform]
R_fixture= 0.6000k
V_fixture= 0.0
V_fixture_min= 0.0
V_fixture_max= 0.0
|time   V(typ)   V(min)   V(max)
0s        47.1nV     1.315uV    17.96nV
2.2ns     -7.204mV   -18.64mV   23.54mV
2.559ns   -3.132mV   -10.26mV   357.9mV
3.428ns   285.1mV    -4.508mV   1.748V
4.147ns   999.4mV    4.193mV    1.895V
4.631ns   1.482V     66.43mV    1.907V
5.04ns    1.647V     183.7mV    1.912V
7.395ns   1.718V     1.394V     1.922V
8.854ns   1.725V     1.56V      1.924V
60ns      1.733V     1.622V     1.926V
[Rising Waveform]
R_fixture= 0.6000k
V_fixture= 1.8000
V_fixture_min= 1.7100
V_fixture_max= 1.9800
|time   V(typ)   V(min)   V(max)
0s        72.29mV    95.11mV    58.66mV
1.133ns   71.85mV    95.04mV    53.51mV
1.436ns   71.79mV    94.69mV    403mV
2.123ns   560.6mV    94.56mV    784.2mV
3.071ns   940.7mV    624.5mV    1.854V
3.541ns   1.235V     783.9mV    1.971V
4.362ns   1.762V     1.02V      1.978V
6.044ns   1.797V     1.603V     1.979V
7.007ns   1.798V     1.698V     1.98V
60ns      1.8V       1.71V      1.98V
[Falling Waveform]
R_fixture= 0.6000k
V_fixture= 0.0
V_fixture_min= 0.0
V_fixture_max= 0.0
|time   V(typ)   V(min)   V(max)
0s        1.733V     1.622V     1.926V
1.454ns   1.734V     1.622V     1.93V
1.909ns   1.724V     1.621V     1.454V
2.797ns   1.063V     1.599V     885.8mV
3.54ns    750.1mV    1.088V     122.7mV
4.235ns   214.5mV    824.6mV    13.89mV
4.668ns   47.91mV    702.5mV    6.091mV
5.939ns   6.278mV    110mV      1.139mV
7.169ns   2.39mV     13.58mV    331.3uV
60ns      2.987uV    6.212uV    1.311uV
[Falling Waveform]
R_fixture= 0.6000k
V_fixture= 1.8000
V_fixture_min= 1.7100
V_fixture_max= 1.9800
|time   V(typ)   V(min)   V(max)
0s        1.8V       1.71V      1.98V
2.67ns    1.819V     1.72V      1.964V
2.974ns   1.813V     1.742V     1.721V
3.346ns   1.744V     1.736V     1.106V
3.907ns   1.292V     1.724V     225.3mV
4.787ns   321.7mV    1.558V     83.3mV
5.271ns   144.6mV    1.285V     72.55mV
6.716ns   90.08mV    300.6mV    62.64mV
8.167ns   79.89mV    138.2mV    60.1mV
60ns      72.29mV    95.12mV    58.66mV
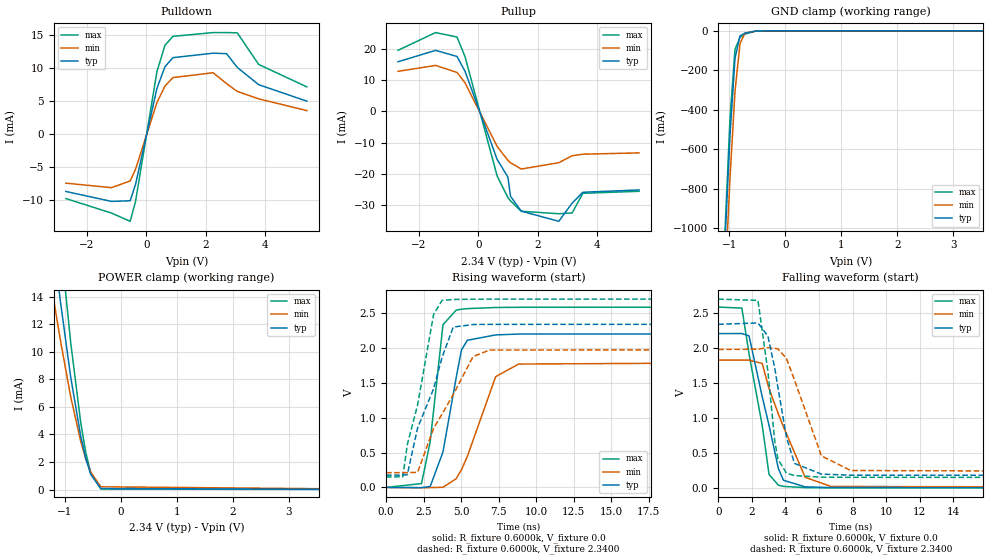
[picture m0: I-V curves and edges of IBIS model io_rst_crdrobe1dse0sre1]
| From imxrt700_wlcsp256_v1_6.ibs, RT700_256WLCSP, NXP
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[Model] io_rst_crdrobe1dse0sre1
|   Model io_rst_crdrobe1dse0sre1
| This model was characterised for following simulation conditions:
| External (pad) voltage:
|   - Typ: 2.34V,   - Min: 1.98V,   - Max: 2.7V
| Library cells for typ/min/max conditions are connected as defined below:
|  PAD_RST - External Pad
|  ipp_do - Core Input
|  ipp_obe - Output Buffer Enable
|  ASRCN3V3[3] - NC
|  ASRCN3V3[4] - NC
|  ASRCP3V3[4] - NC
|  REFAPBIAS3V3 - gnde
|  REFBAMPL3V3 - vdd1v8
|  REFCAMPH3V3 - vdd1v8
|  REFDNBIAS3V3 - vdd1v8
|  REFH3V3 - REFH3V3
|  REFL3V3 - REFL3V3
|  gnde - gnde
|  ipp_dse - gnde
|  ipp_ina235_3v - NC
|  ipp_ina40_3v - NC
|  ipp_ina_mux - NC
|  ipp_ind - NC
|  ipp_ind_1p8v - NC
|  ipp_ind_3v - NC
|  ipp_sre - vdd
|  vdd - vdd
|  vdd1v8 - vdd1v8
|  vdda - vdde3v3
|  vdde3v3 - vdde3v3
| All other pins connected to ground
Model_type I/O
Polarity   Non-Inverting
Enable   Active-High
Vinl =   0.7020V
Vinh =   1.6300V
Vmeas =  1.1700V
Cref =   15.0000pF
Rref =   0.6000k
Vref =   0.0V
C_comp   3.9956pF   3.8199pF   4.1038pF
|C_comp_pullup   0.5142pF   0.5882pF   0.4996pF
|C_comp_pulldown   2.0716pF   2.1607pF   1.8542pF
[Model Spec]
| variable   typ   min   max
Vinh   1.6300V   NA   NA
Vinl   0.7020V   NA   NA
Vref   0.0V   0.0V   0.0V
Cref   15.0000pF   15.0000pF   15.0000pF
Rref   0.6000k   0.6000k   0.6000k
[Receiver Thresholds]
Vcross_high  =   0.0V
Vcross_low  =   0.0V
Vdiff_ac  =   0.0V
Vdiff_dc  =   0.0V
Tdiffslew_ac  =   0.0S
[Temperature Range]   25.0000   0.1250k   -40.0000
[Voltage Range]   2.3400V   1.9800V   2.7000V
[Pullup Reference]   2.3400V   1.9800V   2.7000V
[Pulldown Reference]   0.0V   0.0V   0.0V
[POWER Clamp Reference]   2.3400V   1.9800V   2.7000V
[GND Clamp Reference]   0.0V   0.0V   0.0V
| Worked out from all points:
|   slope of the pulldown table from 0 to 0.351 V, typ, clamps not added: 51.9 ohm
|   slope of the pullup table from 0 to 0.351 V, typ, clamps not added: 37.8 ohm
|   GND clamp passes 1 mA (typ) near -0.49 V on its own axis
|   POWER clamp passes 1 mA (typ) near -0.53 V on its own axis
|   rising waveform, R_fixture 0.6000k, V_fixture 0.0: 20-80 % time 1.1ns typ, 1.77ns min, 784ps max; typ from 0 V to 2.21 V
|   rising waveform, R_fixture 0.6000k, V_fixture 2.3400: 20-80 % time 2ns typ, 2.66ns min, 1.48ns max; typ from 0.177 V to 2.34 V
|   falling waveform, R_fixture 0.6000k, V_fixture 0.0: 20-80 % time 1.29ns typ, 1.78ns min, 1.09ns max; typ from 2.21 V to 0 V
|   falling waveform, R_fixture 0.6000k, V_fixture 2.3400: 20-80 % time 977ps typ, 1.48ns min, 649ps max; typ from 2.34 V to 0.177 V
[Pulldown]
|Voltage   I(typ)   I(min)   I(max)
-2.7V     -8.67mA    -7.41mA    -9.74mA
-1.17V    -10.17mA   -8.095mA   -11.93mA
-540mV    -10.08mA   -7.082mA   -13.18mA
-360mV    -7.618mA   -5.325mA   -10.21mA
360mV     6.913mA    4.777mA    9.448mA
630mV     10.2mA     7.277mA    13.44mA
900mV     11.57mA    8.553mA    14.79mA
2.25V     12.24mA    9.288mA    15.36mA
2.7V      12.17mA    7.637mA    15.36mA
3.06V     10.09mA    6.461mA    15.32mA
3.78V     7.479mA    5.34mA     10.54mA
5.4V      4.985mA    3.556mA    7.138mA
[Pullup]
|Voltage   I(typ)   I(min)   I(max)
-2.7V     15.88mA    12.82mA    19.56mA
-1.44V    19.54mA    14.7mA     25.24mA
-720mV    17.58mA    12.48mA    23.82mA
-450mV    12.84mA    9.141mA    17.52mA
630mV     -15.42mA   -11.25mA   -20.73mA
990mV     -21.04mA   -15.7mA    -27.62mA
1.08V     -27.24mA   -16.49mA   -28.69mA
1.44V     -31.99mA   -18.49mA   -32.03mA
2.7V      -35.24mA   -16.46mA   -32.81mA
3.15V     -29.4mA    -14.24mA   -32.57mA
3.51V     -25.93mA   -13.74mA   -26.26mA
5.4V      -25.18mA   -13.31mA   -25.63mA
[GND_clamp]
|Voltage   I(typ)   I(min)   I(max)
-2.7V     -12.91A    -12.88A    -13.56A
-1.08V    -1.077A    -1.286A    -1.025A
-990mV    -533.6mA   -749.4mA   -449.1mA
-900mV    -139.2mA   -307mA     -94.25mA
-810mV    -25.49mA   -63.91mA   -32.87mA
-720mV    -11.78mA   -11.41mA   -16.65mA
-540mV    -1.684mA   -1.901mA   -2.149mA
-360mV    -36.04uA   -133.3uA   -15.05uA
5.4V      0A         0A         0A
[POWER_clamp]
|Voltage   I(typ)   I(min)   I(max)
-2.7V     73.96mA    57.58mA    95.4mA
-1.44V    26.15mA    20.18mA    34.67mA
-1.35V    22.86mA    17.7mA     30.34mA
-1.26V    19.66mA    15.3mA     26.09mA
-1.17V    16.56mA    12.98mA    21.97mA
-1.08V    13.59mA    10.78mA    17.99mA
-900mV    8.212mA    6.776mA    10.73mA
-720mV    3.9mA      3.518mA    4.888mA
-630mV    2.284mA    2.252mA    2.724mA
-540mV    1.103mA    1.268mA    1.195mA
-360mV    77.93uA    204.3uA    41.52uA
5.4V      0A         0A         0A
[Ramp]
| variable   typ   min   max
dV/dt_r  1.3244/1.0967n   1.0970/1.7714n   1.5519/0.7842n
dV/dt_f  1.2978/0.9774n   1.0605/1.4830n   1.5299/0.6485n
R_load = 0.6000k
[Rising Waveform]
R_fixture= 0.6000k
V_fixture= 0.0
V_fixture_min= 0.0
V_fixture_max= 0.0
|time   V(typ)   V(min)   V(max)
0s        133.2nV    3.451uV    44.06nV
2.364ns   -1.902mV   -6.029mV   55.52mV
2.943ns   13.35mV    -2.163mV   654.4mV
3.795ns   508.5mV    2.281mV    2.333V
4.676ns   1.575V     125.3mV    2.543V
5.026ns   1.97V      252.6mV    2.555V
5.419ns   2.11V      445.1mV    2.564V
7.305ns   2.187V     1.588V     2.58V
8.833ns   2.199V     1.769V     2.583V
60ns      2.207V     1.828V     2.587V
[Rising Waveform]
R_fixture= 0.6000k
V_fixture= 2.3400
V_fixture_min= 1.9800
V_fixture_max= 2.7000
|time   V(typ)   V(min)   V(max)
0s        177mV      212.5mV    150.2mV
1.118ns   176mV      212.4mV    152.5mV
1.418ns   183.8mV    211.9mV    613.5mV
2.104ns   852.3mV    216.8mV    1.183V
3.169ns   1.415V     847.6mV    2.479V
3.732ns   1.864V     1.051V     2.682V
4.48ns    2.299V     1.332V     2.695V
5.798ns   2.336V     1.876V     2.699V
6.893ns   2.338V     1.97V      2.7V
60ns      2.34V      1.98V      2.7V
[Falling Waveform]
R_fixture= 0.6000k
V_fixture= 0.0
V_fixture_min= 0.0
V_fixture_max= 0.0
|time   V(typ)   V(min)   V(max)
0s        2.207V     1.828V     2.586V
1.409ns   2.208V     1.828V     2.572V
1.835ns   2.175V     1.827V     1.917V
2.619ns   1.305V     1.78V      894.5mV
3.029ns   890.5mV    1.417V     191.1mV
3.583ns   274.2mV    1.056V     38.34mV
3.887ns   108.5mV    873mV      20.99mV
5.174ns   14.19mV    151.5mV    3.218mV
6.726ns   4.155mV    19.45mV    520.9uV
60ns      6.176uV    16.83uV    1.379uV
[Falling Waveform]
R_fixture= 0.6000k
V_fixture= 2.3400
V_fixture_min= 1.9800
V_fixture_max= 2.7000
|time   V(typ)   V(min)   V(max)
0s        2.34V      1.98V      2.7V
2.367ns   2.359V     1.984V     2.682V
2.959ns   2.171V     2.006V     1.665V
3.366ns   1.714V     1.995V     670.7mV
3.554ns   1.437V     1.989V     411mV
4.064ns   725.5mV    1.851V     209.7mV
4.54ns    350.2mV    1.543V     175.8mV
6.146ns   196.2mV    456.7mV    153.2mV
7.892ns   181.6mV    248.1mV    150.6mV
60ns      177mV      212.6mV    150.2mV
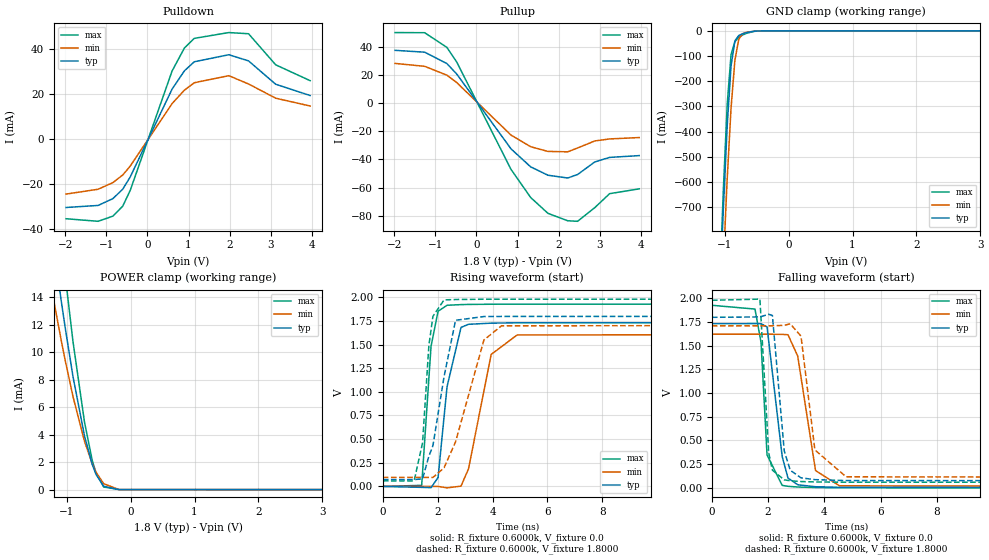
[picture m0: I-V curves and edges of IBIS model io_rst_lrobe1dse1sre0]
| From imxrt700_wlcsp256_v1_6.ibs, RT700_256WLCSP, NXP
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[Model] io_rst_lrobe1dse1sre0
|   Model io_rst_lrobe1dse1sre0
| This model was characterised for following simulation conditions:
| External (pad) voltage:
|   - Typ: 1.8V,   - Min: 1.71V,   - Max: 1.98V
| Library cells for typ/min/max conditions are connected as defined below:
|  PAD_RST - External Pad
|  ipp_do - Core Input
|  ipp_obe - Output Buffer Enable
|  ASRCN3V3[3] - NC
|  ASRCN3V3[4] - NC
|  ASRCP3V3[4] - NC
|  REFAPBIAS3V3 - gnde
|  REFBAMPL3V3 - vdd1v8
|  REFCAMPH3V3 - vdd1v8
|  REFDNBIAS3V3 - vdd1v8
|  REFH3V3 - REFH3V3
|  REFL3V3 - REFL3V3
|  gnde - gnde
|  ipp_dse - vdd
|  ipp_ina235_3v - NC
|  ipp_ina40_3v - NC
|  ipp_ina_mux - NC
|  ipp_ind - NC
|  ipp_ind_1p8v - NC
|  ipp_ind_3v - NC
|  ipp_sre - gnde
|  vdd - vdd
|  vdd1v8 - vdd1v8
|  vdda - vdde3v3
|  vdde3v3 - vdde3v3
| All other pins connected to ground
Model_type I/O
Polarity   Non-Inverting
Enable   Active-High
Vinl =   0.5400V
Vinh =   1.2600V
Vmeas =  0.9000V
Cref =   15.0000pF
Rref =   0.6000k
Vref =   0.0V
C_comp   3.9805pF   3.7965pF   4.1056pF
|C_comp_pullup   0.3212pF   0.4285pF   0.2794pF
|C_comp_pulldown   2.2497pF   2.3231pF   2.0508pF
[Model Spec]
| variable   typ   min   max
Vinh   1.2600V   NA   NA
Vinl   0.5400V   NA   NA
Vref   0.0V   0.0V   0.0V
Cref   15.0000pF   15.0000pF   15.0000pF
Rref   0.6000k   0.6000k   0.6000k
[Receiver Thresholds]
Vcross_high  =   0.0V
Vcross_low  =   0.0V
Vdiff_ac  =   0.0V
Vdiff_dc  =   0.0V
Tdiffslew_ac  =   0.0S
[Temperature Range]   25.0000   0.1250k   -40.0000
[Voltage Range]   1.8000V   1.7100V   1.9800V
[Pullup Reference]   1.8000V   1.7100V   1.9800V
[Pulldown Reference]   0.0V   0.0V   0.0V
[POWER Clamp Reference]   1.8000V   1.7100V   1.9800V
[GND Clamp Reference]   0.0V   0.0V   0.0V
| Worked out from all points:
|   slope of the pulldown table from 0 to 0.27 V, typ, clamps not added: 25.6 ohm
|   slope of the pullup table from 0 to 0.27 V, typ, clamps not added: 23.7 ohm
|   GND clamp passes 1 mA (typ) near -0.50 V on its own axis
|   POWER clamp passes 1 mA (typ) near -0.53 V on its own axis
|   rising waveform, R_fixture 0.6000k, V_fixture 0.0: 20-80 % time 368ps typ, 613ps min, 256ps max; typ from 0 V to 1.73 V
|   rising waveform, R_fixture 0.6000k, V_fixture 1.8000: 20-80 % time 547ps typ, 991ps min, 279ps max; typ from 0.072 V to 1.8 V
|   falling waveform, R_fixture 0.6000k, V_fixture 0.0: 20-80 % time 289ps typ, 437ps min, 208ps max; typ from 1.73 V to 0 V
|   falling waveform, R_fixture 0.6000k, V_fixture 1.8000: 20-80 % time 244ps typ, 372ps min, 177ps max; typ from 1.8 V to 0.072 V
[Pulldown]
|Voltage   I(typ)   I(min)   I(max)
-1.98V    -30.4mA    -24.44mA   -35.4mA
-1.2V     -29.49mA   -22.29mA   -36.54mA
-840mV    -26.45mA   -19.34mA   -34.25mA
-600mV    -22.26mA   -15.94mA   -29.79mA
-420mV    -16.87mA   -12.03mA   -22.87mA
600mV     22.22mA    15.79mA    30.28mA
900mV     30.36mA    21.79mA    40.52mA
1.14V     34.39mA    25.07mA    44.8mA
1.98V     37.52mA    28.21mA    47.38mA
2.46V     34.79mA    24.52mA    46.86mA
3.12V     24.41mA    18.2mA     33.05mA
3.96V     19.38mA    14.72mA    25.98mA
[Pullup]
|Voltage   I(typ)   I(min)   I(max)
-1.98V    37.48mA    28.19mA    50.1mA
-1.26V    36.17mA    26.14mA    50mA
-720mV    28.12mA    19.85mA    39.61mA
-480mV    20.68mA    14.63mA    29.2mA
840mV     -32.44mA   -22.67mA   -46.99mA
1.32V     -45.27mA   -30.96mA   -67.03mA
1.74V     -51.2mA    -34.29mA   -78.26mA
2.22V     -53.17mA   -34.57mA   -83.53mA
2.46V     -50.7mA    -31.84mA   -83.91mA
2.88V     -41.76mA   -26.86mA   -74.2mA
3.24V     -38.54mA   -25.42mA   -64.28mA
3.96V     -37.26mA   -24.44mA   -60.88mA
[GND_clamp]
|Voltage   I(typ)   I(min)   I(max)
-1.98V    -7.543A    -7.6A      -7.897A
-1.08V    -1.077A    -1.286A    -1.025A
-1.02V    -705.3mA   -921.3mA   -628.8mA
-960mV    -377.1mA   -587.4mA   -291.7mA
-900mV    -139.2mA   -307mA     -94.38mA
-840mV    -40.12mA   -117mA     -42.82mA
-780mV    -18.81mA   -33.95mA   -26.13mA
-720mV    -11.86mA   -11.44mA   -16.78mA
-660mV    -7.061mA   -5.737mA   -9.992mA
-540mV    -1.684mA   -1.901mA   -2.15mA
-420mV    -207.1uA   -403.7uA   -160.6uA
3.96V     0A         0A         0A
[POWER_clamp]
|Voltage   I(typ)   I(min)   I(max)
-1.98V    46.79mA    35.95mA    61.44mA
-1.32V    21.78mA    16.85mA    28.96mA
-1.2V     17.57mA    13.71mA    23.37mA
-1.08V    13.59mA    10.75mA    18.03mA
-1.02V    11.71mA    9.354mA    15.49mA
-900mV    8.21mA     6.76mA     10.75mA
-720mV    3.899mA    3.511mA    4.896mA
-600mV    1.839mA    1.889mA    2.143mA
-540mV    1.103mA    1.267mA    1.197mA
-420mV    244.5uA    429.3uA    190.7uA
-180mV    281nA      5.273uA    27.6nA
3.96V     0A         0A         0A
[Ramp]
| variable   typ   min   max
dV/dt_r  1.0397/0.3679n   0.9731/0.6129n   1.1565/0.2557n
dV/dt_f  1.0366/0.2441n   0.9689/0.3724n   1.1528/0.1770n
R_load = 0.6000k
[Rising Waveform]
R_fixture= 0.6000k
V_fixture= 0.0
V_fixture_min= 0.0
V_fixture_max= 0.0
|time   V(typ)   V(min)   V(max)
0s        48.77nV    1.315uV    52.41nV
1.416ns   -9.948mV   -393.8uV   11.27mV
1.757ns   -12.87mV   -506uV     1.481V
2.014ns   94.24mV    30.57uV    1.852V
2.34ns    1.053V     -15.27mV   1.915V
2.85ns    1.681V     2.996mV    1.922V
3.124ns   1.714V     186.5mV    1.924V
3.949ns   1.726V     1.395V     1.926V
4.896ns   1.73V      1.601V     1.927V
60ns      1.733V     1.622V     1.927V
[Rising Waveform]
R_fixture= 0.6000k
V_fixture= 1.8000
V_fixture_min= 1.7100
V_fixture_max= 1.9800
|time   V(typ)   V(min)   V(max)
0s        72.28mV    95.11mV    58.66mV
1.141ns   71.88mV    95.03mV    58.11mV
1.448ns   80.83mV    94.67mV    461.3mV
1.678ns   318.7mV    94.64mV    1.488V
1.826ns   430.6mV    94.79mV    1.798V
2.232ns   1.161V     196.6mV    1.972V
2.651ns   1.756V     471.2mV    1.976V
3.685ns   1.796V     1.548V     1.979V
4.328ns   1.797V     1.698V     1.979V
60ns      1.8V       1.71V      1.98V
[Falling Waveform]
R_fixture= 0.6000k
V_fixture= 0.0
V_fixture_min= 0.0
V_fixture_max= 0.0
|time   V(typ)   V(min)   V(max)
0s        1.733V     1.622V     1.927V
1.533ns   1.734V     1.622V     1.887V
1.748ns   1.733V     1.621V     1.535V
1.962ns   1.698V     1.622V     347mV
2.501ns   329.3mV    1.62V      25.84mV
2.707ns   103.3mV    1.616V     16.41mV
3.052ns   32.78mV    1.391V     8.879mV
3.685ns   11.83mV    183mV      3.482mV
4.536ns   5.171mV    21.46mV    1.214mV
60ns      2.969uV    6.182uV    1.434uV
[Falling Waveform]
R_fixture= 0.6000k
V_fixture= 1.8000
V_fixture_min= 1.7100
V_fixture_max= 1.9800
|time   V(typ)   V(min)   V(max)
0s        1.8V       1.71V      1.98V
1.708ns   1.804V     1.71V      1.992V
2.021ns   1.832V     1.71V      369mV
2.152ns   1.82V      1.711V     186.4mV
2.573ns   391.6mV    1.715V     84.72mV
2.785ns   186.4mV    1.732V     74.96mV
3.168ns   105.7mV    1.602V     66.85mV
3.663ns   86.65mV    399.9mV    62.54mV
4.774ns   76.83mV    116.6mV    59.63mV
60ns      72.29mV    95.11mV    58.66mV
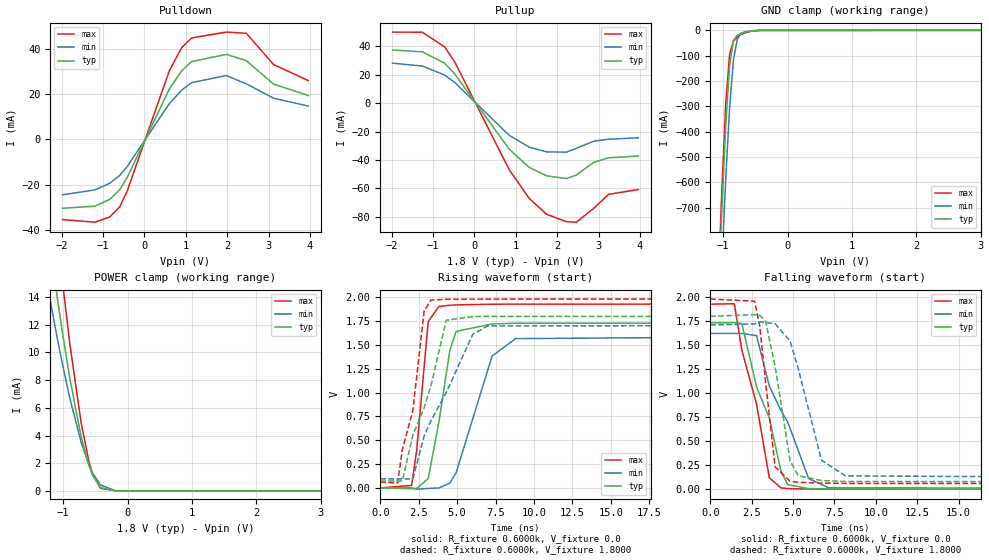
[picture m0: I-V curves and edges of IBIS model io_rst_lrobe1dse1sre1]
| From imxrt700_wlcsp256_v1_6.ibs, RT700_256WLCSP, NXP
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[Model] io_rst_lrobe1dse1sre1
|   Model io_rst_lrobe1dse1sre1
| This model was characterised for following simulation conditions:
| External (pad) voltage:
|   - Typ: 1.8V,   - Min: 1.71V,   - Max: 1.98V
| Library cells for typ/min/max conditions are connected as defined below:
|  PAD_RST - External Pad
|  ipp_do - Core Input
|  ipp_obe - Output Buffer Enable
|  ASRCN3V3[3] - NC
|  ASRCN3V3[4] - NC
|  ASRCP3V3[4] - NC
|  REFAPBIAS3V3 - gnde
|  REFBAMPL3V3 - vdd1v8
|  REFCAMPH3V3 - vdd1v8
|  REFDNBIAS3V3 - vdd1v8
|  REFH3V3 - REFH3V3
|  REFL3V3 - REFL3V3
|  gnde - gnde
|  ipp_dse - vdd
|  ipp_ina235_3v - NC
|  ipp_ina40_3v - NC
|  ipp_ina_mux - NC
|  ipp_ind - NC
|  ipp_ind_1p8v - NC
|  ipp_ind_3v - NC
|  ipp_sre - vdd
|  vdd - vdd
|  vdd1v8 - vdd1v8
|  vdda - vdde3v3
|  vdde3v3 - vdde3v3
| All other pins connected to ground
Model_type I/O
Polarity   Non-Inverting
Enable   Active-High
Vinl =   0.5400V
Vinh =   1.2600V
Vmeas =  0.9000V
Cref =   15.0000pF
Rref =   0.6000k
Vref =   0.0V
C_comp   3.9805pF   3.7965pF   4.1056pF
|C_comp_pullup   0.3209pF   0.4282pF   0.2792pF
|C_comp_pulldown   2.2499pF   2.3233pF   2.0511pF
[Model Spec]
| variable   typ   min   max
Vinh   1.2600V   NA   NA
Vinl   0.5400V   NA   NA
Vref   0.0V   0.0V   0.0V
Cref   15.0000pF   15.0000pF   15.0000pF
Rref   0.6000k   0.6000k   0.6000k
[Receiver Thresholds]
Vcross_high  =   0.0V
Vcross_low  =   0.0V
Vdiff_ac  =   0.0V
Vdiff_dc  =   0.0V
Tdiffslew_ac  =   0.0S
[Temperature Range]   25.0000   0.1250k   -40.0000
[Voltage Range]   1.8000V   1.7100V   1.9800V
[Pullup Reference]   1.8000V   1.7100V   1.9800V
[Pulldown Reference]   0.0V   0.0V   0.0V
[POWER Clamp Reference]   1.8000V   1.7100V   1.9800V
[GND Clamp Reference]   0.0V   0.0V   0.0V
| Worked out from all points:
|   slope of the pulldown table from 0 to 0.27 V, typ, clamps not added: 25.6 ohm
|   slope of the pullup table from 0 to 0.27 V, typ, clamps not added: 23.7 ohm
|   GND clamp passes 1 mA (typ) near -0.50 V on its own axis
|   POWER clamp passes 1 mA (typ) near -0.53 V on its own axis
|   rising waveform, R_fixture 0.6000k, V_fixture 0.0: 20-80 % time 1ns typ, 1.75ns min, 621ps max; typ from 0 V to 1.73 V
|   rising waveform, R_fixture 0.6000k, V_fixture 1.8000: 20-80 % time 1.96ns typ, 2.85ns min, 1.19ns max; typ from 0.072 V to 1.8 V
|   falling waveform, R_fixture 0.6000k, V_fixture 0.0: 20-80 % time 1.8ns typ, 2.26ns min, 1.51ns max; typ from 1.73 V to 0 V
|   falling waveform, R_fixture 0.6000k, V_fixture 1.8000: 20-80 % time 940ps typ, 1.38ns min, 693ps max; typ from 1.8 V to 0.072 V
[Pulldown]
|Voltage   I(typ)   I(min)   I(max)
-1.98V    -30.4mA    -24.44mA   -35.4mA
-1.2V     -29.49mA   -22.29mA   -36.54mA
-840mV    -26.45mA   -19.34mA   -34.25mA
-600mV    -22.26mA   -15.94mA   -29.79mA
-420mV    -16.87mA   -12.03mA   -22.87mA
600mV     22.22mA    15.79mA    30.28mA
900mV     30.36mA    21.79mA    40.52mA
1.14V     34.39mA    25.07mA    44.8mA
1.98V     37.52mA    28.2mA     47.38mA
2.46V     34.79mA    24.52mA    46.86mA
3.12V     24.41mA    18.2mA     33.05mA
3.96V     19.38mA    14.72mA    25.98mA
[Pullup]
|Voltage   I(typ)   I(min)   I(max)
-1.98V    37.48mA    28.19mA    50.1mA
-1.26V    36.17mA    26.14mA    50mA
-720mV    28.12mA    19.85mA    39.61mA
-480mV    20.68mA    14.63mA    29.2mA
840mV     -32.44mA   -22.67mA   -46.99mA
1.32V     -45.27mA   -30.96mA   -67.03mA
1.74V     -51.2mA    -34.29mA   -78.26mA
2.22V     -53.16mA   -34.57mA   -83.53mA
2.46V     -50.7mA    -31.83mA   -83.9mA
2.88V     -41.75mA   -26.85mA   -74.19mA
3.24V     -38.52mA   -25.41mA   -64.26mA
3.96V     -37.23mA   -24.42mA   -60.85mA
[GND_clamp]
|Voltage   I(typ)   I(min)   I(max)
-1.98V    -7.543A    -7.6A      -7.897A
-1.08V    -1.077A    -1.286A    -1.025A
-1.02V    -705.3mA   -921.3mA   -628.8mA
-960mV    -377.1mA   -587.4mA   -291.7mA
-900mV    -139.2mA   -307mA     -94.38mA
-840mV    -40.12mA   -117mA     -42.82mA
-780mV    -18.81mA   -33.95mA   -26.13mA
-720mV    -11.86mA   -11.44mA   -16.78mA
-660mV    -7.061mA   -5.737mA   -9.992mA
-540mV    -1.684mA   -1.901mA   -2.15mA
-420mV    -207.1uA   -403.7uA   -160.6uA
3.96V     0A         0A         0A
[POWER_clamp]
|Voltage   I(typ)   I(min)   I(max)
-1.98V    46.79mA    35.95mA    61.44mA
-1.32V    21.78mA    16.85mA    28.96mA
-1.2V     17.57mA    13.71mA    23.37mA
-1.08V    13.59mA    10.75mA    18.03mA
-1.02V    11.71mA    9.354mA    15.49mA
-900mV    8.21mA     6.76mA     10.75mA
-720mV    3.899mA    3.511mA    4.896mA
-600mV    1.839mA    1.889mA    2.143mA
-540mV    1.103mA    1.267mA    1.197mA
-420mV    244.5uA    429.3uA    190.7uA
-180mV    281nA      5.273uA    27.6nA
3.96V     0A         0A         0A
[Ramp]
| variable   typ   min   max
dV/dt_r  1.0397/0.9995n   0.9731/1.7461n   1.1565/0.6209n
dV/dt_f  1.0366/0.9396n   0.9689/1.3837n   1.1528/0.6931n
R_load = 0.6000k
[Rising Waveform]
R_fixture= 0.6000k
V_fixture= 0.0
V_fixture_min= 0.0
V_fixture_max= 0.0
|time   V(typ)   V(min)   V(max)
0s        48.77nV    1.315uV    52.41nV
2.042ns   -8.483mV   -148uV     25.54mV
2.361ns   -6.011mV   -13.66mV   384.2mV
3.12ns    97.68mV    -6.008mV   1.745V
3.811ns   684.8mV    -1.931mV   1.902V
4.526ns   1.44V      49.29mV    1.915V
4.937ns   1.641V     159mV      1.919V
7.277ns   1.719V     1.382V     1.926V
8.798ns   1.726V     1.565V     1.927V
60ns      1.733V     1.622V     1.927V
[Rising Waveform]
R_fixture= 0.6000k
V_fixture= 1.8000
V_fixture_min= 1.7100
V_fixture_max= 1.9800
|time   V(typ)   V(min)   V(max)
0s        72.28mV    95.11mV    58.66mV
1.133ns   71.85mV    95.04mV    53.24mV
1.438ns   71.78mV    94.68mV    401.1mV
2.121ns   555.8mV    93.97mV    812.4mV
2.854ns   840.8mV    544.5mV    1.855V
3.293ns   1.069V     702.4mV    1.97V
4.293ns   1.758V     1V         1.978V
6.018ns   1.797V     1.609V     1.979V
6.973ns   1.798V     1.698V     1.98V
60ns      1.8V       1.71V      1.98V
[Falling Waveform]
R_fixture= 0.6000k
V_fixture= 0.0
V_fixture_min= 0.0
V_fixture_max= 0.0
|time   V(typ)   V(min)   V(max)
0s        1.733V     1.622V     1.927V
1.452ns   1.734V     1.622V     1.931V
1.906ns   1.725V     1.622V     1.448V
2.797ns   1.064V     1.599V     883.6mV
3.566ns   738.8mV    1.074V     118.5mV
4.266ns   189.9mV    819mV      13.26mV
4.677ns   46.57mV    699.4mV    6.141mV
5.939ns   6.256mV    109.8mV    1.155mV
7.166ns   2.381mV    13.59mV    339uV
60ns      3.232uV    6.49uV     1.926uV
[Falling Waveform]
R_fixture= 0.6000k
V_fixture= 1.8000
V_fixture_min= 1.7100
V_fixture_max= 1.9800
|time   V(typ)   V(min)   V(max)
0s        1.8V       1.71V      1.98V
2.677ns   1.818V     1.721V     1.958V
2.992ns   1.811V     1.742V     1.693V
3.345ns   1.744V     1.735V     1.104V
3.918ns   1.278V     1.722V     231.5mV
4.819ns   296.8mV    1.543V     82.4mV
5.315ns   139.7mV    1.254V     71.98mV
6.715ns   90.06mV    301mV      62.65mV
8.163ns   79.89mV    138.2mV    60.09mV
60ns      72.29mV    95.11mV    58.66mV
